VERSION 5.7 ;
NOWIREEXTENSIONATPIN ON ;
DIVIDERCHAR "/" ;
BUSBITCHARS "[]" ;

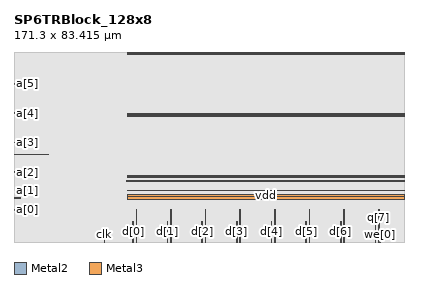
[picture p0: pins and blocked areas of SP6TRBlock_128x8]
MACRO SP6TRBlock_128x8
  CLASS BLOCK ;
  FOREIGN SP6TRBlock_128x8 ;
  ORIGIN 0.000 0.000 ;
  SIZE 171.300 BY 83.415 ;
  SYMMETRY X Y R90 ;
  PIN clk
  USE CLOCK ;
  DIRECTION INPUT ;
  ANTENNAGATEAREA 0.492800 ;
  PORT
      LAYER Metal2 ;
      RECT 39.515 0.000 39.895 1.900 ;
  END
  END clk
  PIN a[0]
  USE SIGNAL ;
  DIRECTION INPUT ;
  ANTENNAGATEAREA 0.492800 ;
  PORT
      LAYER Metal3 ;
      RECT 0.000 14.025 2.980 14.305 ;
  END
  END a[0]
  PIN a[1]
  USE SIGNAL ;
  DIRECTION INPUT ;
  ANTENNAGATEAREA 0.492800 ;
  PORT
      LAYER Metal3 ;
      RECT 0.000 19.165 2.980 19.445 ;
  END
  END a[1]
  PIN a[2]
  USE SIGNAL ;
  DIRECTION INPUT ;
  ANTENNAGATEAREA 0.492800 ;
  PORT
      LAYER Metal3 ;
      RECT 0.000 30.565 2.510 30.845 ;
  END
  END a[2]
  PIN a[3]
  USE SIGNAL ;
  DIRECTION INPUT ;
  ANTENNAGATEAREA 0.492800 ;
  PORT
      LAYER Metal3 ;
      RECT 0.000 43.485 2.510 43.765 ;
  END
  END a[3]
  PIN a[4]
  USE SIGNAL ;
  DIRECTION INPUT ;
  ANTENNAGATEAREA 0.492800 ;
  PORT
      LAYER Metal3 ;
      RECT 0.000 56.405 2.510 56.685 ;
  END
  END a[4]
  PIN a[5]
  USE SIGNAL ;
  DIRECTION INPUT ;
  ANTENNAGATEAREA 0.492800 ;
  PORT
      LAYER Metal3 ;
      RECT 0.000 69.325 2.510 69.605 ;
  END
  END a[5]
  PIN a[6]
  USE SIGNAL ;
  DIRECTION INPUT ;
  ANTENNAGATEAREA 0.492800 ;
  PORT
      LAYER Metal3 ;
      RECT 0.000 38.345 15.010 38.625 ;
  END
  END a[6]
  PIN d[0]
  USE SIGNAL ;
  DIRECTION INPUT ;
  ANTENNAGATEAREA 0.492800 ;
  PORT
      LAYER Metal3 ;
      RECT 52.130 0.000 52.410 9.140 ;
  END
  END d[0]
  PIN d[1]
  USE SIGNAL ;
  DIRECTION INPUT ;
  ANTENNAGATEAREA 0.492800 ;
  PORT
      LAYER Metal3 ;
      RECT 67.330 0.000 67.610 9.140 ;
  END
  END d[1]
  PIN d[2]
  USE SIGNAL ;
  DIRECTION INPUT ;
  ANTENNAGATEAREA 0.492800 ;
  PORT
      LAYER Metal3 ;
      RECT 82.530 0.000 82.810 9.140 ;
  END
  END d[2]
  PIN d[3]
  USE SIGNAL ;
  DIRECTION INPUT ;
  ANTENNAGATEAREA 0.492800 ;
  PORT
      LAYER Metal3 ;
      RECT 97.730 0.000 98.010 9.140 ;
  END
  END d[3]
  PIN d[4]
  USE SIGNAL ;
  DIRECTION INPUT ;
  ANTENNAGATEAREA 0.492800 ;
  PORT
      LAYER Metal3 ;
      RECT 112.930 0.000 113.210 9.140 ;
  END
  END d[4]
  PIN d[5]
  USE SIGNAL ;
  DIRECTION INPUT ;
  ANTENNAGATEAREA 0.492800 ;
  PORT
      LAYER Metal3 ;
      RECT 128.130 0.000 128.410 9.140 ;
  END
  END d[5]
  PIN d[6]
  USE SIGNAL ;
  DIRECTION INPUT ;
  ANTENNAGATEAREA 0.492800 ;
  PORT
      LAYER Metal3 ;
      RECT 143.330 0.000 143.610 9.140 ;
  END
  END d[6]
  PIN d[7]
  USE SIGNAL ;
  DIRECTION INPUT ;
  ANTENNAGATEAREA 0.492800 ;
  PORT
      LAYER Metal3 ;
      RECT 158.530 0.000 158.810 9.140 ;
  END
  END d[7]
  PIN we[0]
  USE SIGNAL ;
  DIRECTION INPUT ;
  ANTENNAGATEAREA 0.492800 ;
  PORT
      LAYER Metal3 ;
      RECT 160.550 0.000 160.830 1.000 ;
  END
  END we[0]
  PIN q[0]
  USE SIGNAL ;
  DIRECTION OUTPUT ;
  PORT
      LAYER Metal3 ;
      RECT 53.590 0.000 53.870 14.190 ;
  END
  END q[0]
  PIN q[1]
  USE SIGNAL ;
  DIRECTION OUTPUT ;
  PORT
      LAYER Metal3 ;
      RECT 68.790 0.000 69.070 14.190 ;
  END
  END q[1]
  PIN q[2]
  USE SIGNAL ;
  DIRECTION OUTPUT ;
  PORT
      LAYER Metal3 ;
      RECT 83.990 0.000 84.270 14.190 ;
  END
  END q[2]
  PIN q[3]
  USE SIGNAL ;
  DIRECTION OUTPUT ;
  PORT
      LAYER Metal3 ;
      RECT 99.190 0.000 99.470 14.190 ;
  END
  END q[3]
  PIN q[4]
  USE SIGNAL ;
  DIRECTION OUTPUT ;
  PORT
      LAYER Metal3 ;
      RECT 114.390 0.000 114.670 14.190 ;
  END
  END q[4]
  PIN q[5]
  USE SIGNAL ;
  DIRECTION OUTPUT ;
  PORT
      LAYER Metal3 ;
      RECT 129.590 0.000 129.870 14.190 ;
  END
  END q[5]
  PIN q[6]
  USE SIGNAL ;
  DIRECTION OUTPUT ;
  PORT
      LAYER Metal3 ;
      RECT 144.790 0.000 145.070 14.190 ;
  END
  END q[6]
  PIN q[7]
  USE SIGNAL ;
  DIRECTION OUTPUT ;
  PORT
      LAYER Metal3 ;
      RECT 159.990 0.000 160.270 14.190 ;
  END
  END q[7]
  PIN vss
    USE GROUND ;
    DIRECTION INOUT ;
    PORT
      LAYER Metal3 ;
        RECT 49.700 82.195 171.300 82.595 ;
    END
    PORT
      LAYER Metal3 ;
        RECT 49.700 55.235 171.300 55.635 ;
    END
    PORT
      LAYER Metal3 ;
        RECT 49.700 28.275 171.300 28.675 ;
    END
    PORT
      LAYER Metal3 ;
        RECT 49.700 22.450 171.300 22.730 ;
    END
    PORT
      LAYER Metal3 ;
        RECT 49.700 18.780 171.300 19.780 ;
    END
  END vss
  PIN vdd
    USE POWER ;
    DIRECTION INOUT ;
    PORT
      LAYER Metal3 ;
        RECT 49.700 20.060 171.300 21.060 ;
    END
    PORT
      LAYER Metal3 ;
        RECT 49.510 26.745 171.300 27.025 ;
    END
    PORT
      LAYER Metal3 ;
        RECT 49.700 55.915 171.300 56.315 ;
    END
    PORT
      LAYER Metal3 ;
        RECT 49.700 28.955 171.300 29.355 ;
    END
    PORT
      LAYER Metal3 ;
        RECT 49.700 82.875 171.300 83.275 ;
    END
  END vdd
  OBS
    LAYER Metal1 ;
      RECT 0.000 0.000 171.300 83.415 ;
    LAYER Metal2 ;
      RECT 0.000 0.000 171.300 83.415 ;
    LAYER Metal3 ;
      RECT 0.000 0.000 171.300 83.415 ;
  END
END SP6TRBlock_128x8

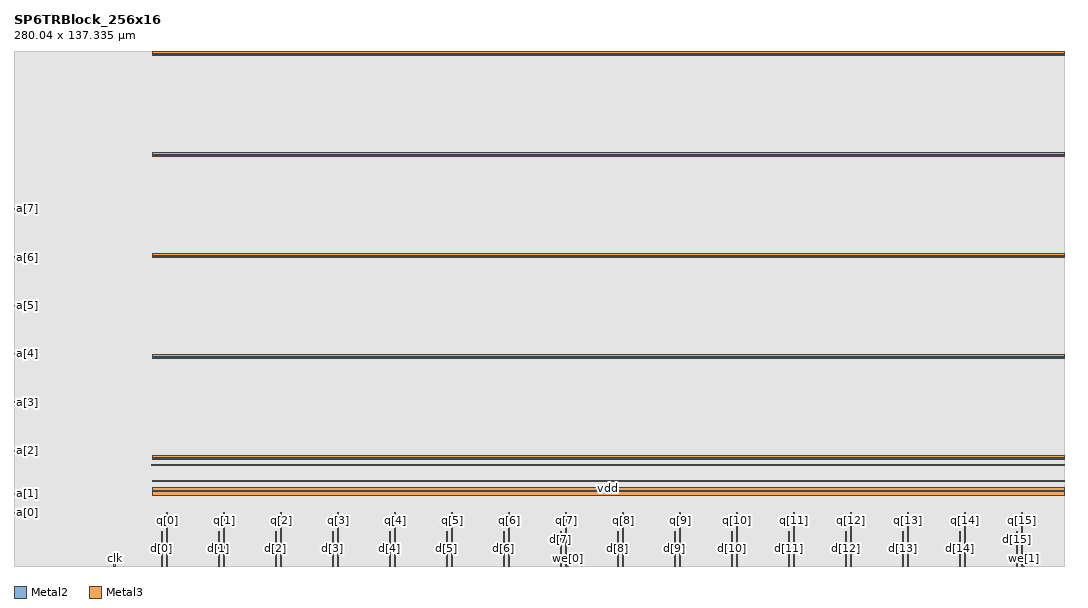
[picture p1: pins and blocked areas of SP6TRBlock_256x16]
MACRO SP6TRBlock_256x16
  CLASS BLOCK ;
  FOREIGN SP6TRBlock_256x16 ;
  ORIGIN 0.000 0.000 ;
  SIZE 280.040 BY 137.335 ;
  SYMMETRY X Y R90 ;
  PIN clk
  USE CLOCK ;
  DIRECTION INPUT ;
  ANTENNAGATEAREA 0.492800 ;
  PORT
      LAYER Metal2 ;
      RECT 26.655 0.000 27.035 1.900 ;
  END
  END clk
  PIN a[0]
  USE SIGNAL ;
  DIRECTION INPUT ;
  ANTENNAGATEAREA 0.492800 ;
  PORT
      LAYER Metal3 ;
      RECT 0.000 14.025 2.980 14.305 ;
  END
  END a[0]
  PIN a[1]
  USE SIGNAL ;
  DIRECTION INPUT ;
  ANTENNAGATEAREA 0.492800 ;
  PORT
      LAYER Metal3 ;
      RECT 0.000 19.165 2.980 19.445 ;
  END
  END a[1]
  PIN a[2]
  USE SIGNAL ;
  DIRECTION INPUT ;
  ANTENNAGATEAREA 0.492800 ;
  PORT
      LAYER Metal3 ;
      RECT 0.000 30.565 2.510 30.845 ;
  END
  END a[2]
  PIN a[3]
  USE SIGNAL ;
  DIRECTION INPUT ;
  ANTENNAGATEAREA 0.492800 ;
  PORT
      LAYER Metal3 ;
      RECT 0.000 43.485 2.510 43.765 ;
  END
  END a[3]
  PIN a[4]
  USE SIGNAL ;
  DIRECTION INPUT ;
  ANTENNAGATEAREA 0.492800 ;
  PORT
      LAYER Metal3 ;
      RECT 0.000 56.405 2.510 56.685 ;
  END
  END a[4]
  PIN a[5]
  USE SIGNAL ;
  DIRECTION INPUT ;
  ANTENNAGATEAREA 0.492800 ;
  PORT
      LAYER Metal3 ;
      RECT 0.000 69.325 2.510 69.605 ;
  END
  END a[5]
  PIN a[6]
  USE SIGNAL ;
  DIRECTION INPUT ;
  ANTENNAGATEAREA 0.492800 ;
  PORT
      LAYER Metal3 ;
      RECT 0.000 82.245 2.510 82.525 ;
  END
  END a[6]
  PIN a[7]
  USE SIGNAL ;
  DIRECTION INPUT ;
  ANTENNAGATEAREA 0.492800 ;
  PORT
      LAYER Metal3 ;
      RECT 0.000 95.165 2.510 95.445 ;
  END
  END a[7]
  PIN d[0]
  USE SIGNAL ;
  DIRECTION INPUT ;
  ANTENNAGATEAREA 0.492800 ;
  PORT
      LAYER Metal3 ;
      RECT 39.270 0.000 39.550 9.140 ;
  END
  END d[0]
  PIN d[1]
  USE SIGNAL ;
  DIRECTION INPUT ;
  ANTENNAGATEAREA 0.492800 ;
  PORT
      LAYER Metal3 ;
      RECT 54.470 0.000 54.750 9.140 ;
  END
  END d[1]
  PIN d[2]
  USE SIGNAL ;
  DIRECTION INPUT ;
  ANTENNAGATEAREA 0.492800 ;
  PORT
      LAYER Metal3 ;
      RECT 69.670 0.000 69.950 9.140 ;
  END
  END d[2]
  PIN d[3]
  USE SIGNAL ;
  DIRECTION INPUT ;
  ANTENNAGATEAREA 0.492800 ;
  PORT
      LAYER Metal3 ;
      RECT 84.870 0.000 85.150 9.140 ;
  END
  END d[3]
  PIN d[4]
  USE SIGNAL ;
  DIRECTION INPUT ;
  ANTENNAGATEAREA 0.492800 ;
  PORT
      LAYER Metal3 ;
      RECT 100.070 0.000 100.350 9.140 ;
  END
  END d[4]
  PIN d[5]
  USE SIGNAL ;
  DIRECTION INPUT ;
  ANTENNAGATEAREA 0.492800 ;
  PORT
      LAYER Metal3 ;
      RECT 115.270 0.000 115.550 9.140 ;
  END
  END d[5]
  PIN d[6]
  USE SIGNAL ;
  DIRECTION INPUT ;
  ANTENNAGATEAREA 0.492800 ;
  PORT
      LAYER Metal3 ;
      RECT 130.470 0.000 130.750 9.140 ;
  END
  END d[6]
  PIN d[7]
  USE SIGNAL ;
  DIRECTION INPUT ;
  ANTENNAGATEAREA 0.492800 ;
  PORT
      LAYER Metal3 ;
      RECT 145.670 0.000 145.950 9.140 ;
  END
  END d[7]
  PIN d[8]
  USE SIGNAL ;
  DIRECTION INPUT ;
  ANTENNAGATEAREA 0.492800 ;
  PORT
      LAYER Metal3 ;
      RECT 160.870 0.000 161.150 9.140 ;
  END
  END d[8]
  PIN d[9]
  USE SIGNAL ;
  DIRECTION INPUT ;
  ANTENNAGATEAREA 0.492800 ;
  PORT
      LAYER Metal3 ;
      RECT 176.070 0.000 176.350 9.140 ;
  END
  END d[9]
  PIN d[10]
  USE SIGNAL ;
  DIRECTION INPUT ;
  ANTENNAGATEAREA 0.492800 ;
  PORT
      LAYER Metal3 ;
      RECT 191.270 0.000 191.550 9.140 ;
  END
  END d[10]
  PIN d[11]
  USE SIGNAL ;
  DIRECTION INPUT ;
  ANTENNAGATEAREA 0.492800 ;
  PORT
      LAYER Metal3 ;
      RECT 206.470 0.000 206.750 9.140 ;
  END
  END d[11]
  PIN d[12]
  USE SIGNAL ;
  DIRECTION INPUT ;
  ANTENNAGATEAREA 0.492800 ;
  PORT
      LAYER Metal3 ;
      RECT 221.670 0.000 221.950 9.140 ;
  END
  END d[12]
  PIN d[13]
  USE SIGNAL ;
  DIRECTION INPUT ;
  ANTENNAGATEAREA 0.492800 ;
  PORT
      LAYER Metal3 ;
      RECT 236.870 0.000 237.150 9.140 ;
  END
  END d[13]
  PIN d[14]
  USE SIGNAL ;
  DIRECTION INPUT ;
  ANTENNAGATEAREA 0.492800 ;
  PORT
      LAYER Metal3 ;
      RECT 252.070 0.000 252.350 9.140 ;
  END
  END d[14]
  PIN d[15]
  USE SIGNAL ;
  DIRECTION INPUT ;
  ANTENNAGATEAREA 0.492800 ;
  PORT
      LAYER Metal3 ;
      RECT 267.270 0.000 267.550 9.140 ;
  END
  END d[15]
  PIN we[0]
  USE SIGNAL ;
  DIRECTION INPUT ;
  ANTENNAGATEAREA 0.492800 ;
  PORT
      LAYER Metal3 ;
      RECT 147.690 0.000 147.970 1.000 ;
  END
  END we[0]
  PIN we[1]
  USE SIGNAL ;
  DIRECTION INPUT ;
  ANTENNAGATEAREA 0.492800 ;
  PORT
      LAYER Metal3 ;
      RECT 269.290 0.000 269.570 1.000 ;
  END
  END we[1]
  PIN q[0]
  USE SIGNAL ;
  DIRECTION OUTPUT ;
  PORT
      LAYER Metal3 ;
      RECT 40.730 0.000 41.010 14.190 ;
  END
  END q[0]
  PIN q[1]
  USE SIGNAL ;
  DIRECTION OUTPUT ;
  PORT
      LAYER Metal3 ;
      RECT 55.930 0.000 56.210 14.190 ;
  END
  END q[1]
  PIN q[2]
  USE SIGNAL ;
  DIRECTION OUTPUT ;
  PORT
      LAYER Metal3 ;
      RECT 71.130 0.000 71.410 14.190 ;
  END
  END q[2]
  PIN q[3]
  USE SIGNAL ;
  DIRECTION OUTPUT ;
  PORT
      LAYER Metal3 ;
      RECT 86.330 0.000 86.610 14.190 ;
  END
  END q[3]
  PIN q[4]
  USE SIGNAL ;
  DIRECTION OUTPUT ;
  PORT
      LAYER Metal3 ;
      RECT 101.530 0.000 101.810 14.190 ;
  END
  END q[4]
  PIN q[5]
  USE SIGNAL ;
  DIRECTION OUTPUT ;
  PORT
      LAYER Metal3 ;
      RECT 116.730 0.000 117.010 14.190 ;
  END
  END q[5]
  PIN q[6]
  USE SIGNAL ;
  DIRECTION OUTPUT ;
  PORT
      LAYER Metal3 ;
      RECT 131.930 0.000 132.210 14.190 ;
  END
  END q[6]
  PIN q[7]
  USE SIGNAL ;
  DIRECTION OUTPUT ;
  PORT
      LAYER Metal3 ;
      RECT 147.130 0.000 147.410 14.190 ;
  END
  END q[7]
  PIN q[8]
  USE SIGNAL ;
  DIRECTION OUTPUT ;
  PORT
      LAYER Metal3 ;
      RECT 162.330 0.000 162.610 14.190 ;
  END
  END q[8]
  PIN q[9]
  USE SIGNAL ;
  DIRECTION OUTPUT ;
  PORT
      LAYER Metal3 ;
      RECT 177.530 0.000 177.810 14.190 ;
  END
  END q[9]
  PIN q[10]
  USE SIGNAL ;
  DIRECTION OUTPUT ;
  PORT
      LAYER Metal3 ;
      RECT 192.730 0.000 193.010 14.190 ;
  END
  END q[10]
  PIN q[11]
  USE SIGNAL ;
  DIRECTION OUTPUT ;
  PORT
      LAYER Metal3 ;
      RECT 207.930 0.000 208.210 14.190 ;
  END
  END q[11]
  PIN q[12]
  USE SIGNAL ;
  DIRECTION OUTPUT ;
  PORT
      LAYER Metal3 ;
      RECT 223.130 0.000 223.410 14.190 ;
  END
  END q[12]
  PIN q[13]
  USE SIGNAL ;
  DIRECTION OUTPUT ;
  PORT
      LAYER Metal3 ;
      RECT 238.330 0.000 238.610 14.190 ;
  END
  END q[13]
  PIN q[14]
  USE SIGNAL ;
  DIRECTION OUTPUT ;
  PORT
      LAYER Metal3 ;
      RECT 253.530 0.000 253.810 14.190 ;
  END
  END q[14]
  PIN q[15]
  USE SIGNAL ;
  DIRECTION OUTPUT ;
  PORT
      LAYER Metal3 ;
      RECT 268.730 0.000 269.010 14.190 ;
  END
  END q[15]
  PIN vss
    USE GROUND ;
    DIRECTION INOUT ;
    PORT
      LAYER Metal3 ;
        RECT 36.840 82.195 280.040 82.595 ;
    END
    PORT
      LAYER Metal3 ;
        RECT 36.840 136.115 280.040 136.515 ;
    END
    PORT
      LAYER Metal3 ;
        RECT 36.840 18.780 280.040 19.780 ;
    END
    PORT
      LAYER Metal3 ;
        RECT 36.840 55.235 280.040 55.635 ;
    END
    PORT
      LAYER Metal3 ;
        RECT 36.840 28.275 280.040 28.675 ;
    END
    PORT
      LAYER Metal3 ;
        RECT 36.840 109.155 280.040 109.555 ;
    END
    PORT
      LAYER Metal3 ;
        RECT 36.840 22.450 280.040 22.730 ;
    END
  END vss
  PIN vdd
    USE POWER ;
    DIRECTION INOUT ;
    PORT
      LAYER Metal3 ;
        RECT 36.840 109.835 280.040 110.235 ;
    END
    PORT
      LAYER Metal3 ;
        RECT 36.840 28.955 280.040 29.355 ;
    END
    PORT
      LAYER Metal3 ;
        RECT 36.650 26.745 280.040 27.025 ;
    END
    PORT
      LAYER Metal3 ;
        RECT 36.840 136.795 280.040 137.195 ;
    END
    PORT
      LAYER Metal3 ;
        RECT 36.840 82.875 280.040 83.275 ;
    END
    PORT
      LAYER Metal3 ;
        RECT 36.840 55.915 280.040 56.315 ;
    END
    PORT
      LAYER Metal3 ;
        RECT 36.840 20.060 280.040 21.060 ;
    END
  END vdd
  OBS
    LAYER Metal1 ;
      RECT 0.000 0.000 280.040 137.335 ;
    LAYER Metal2 ;
      RECT 0.000 0.000 280.040 137.335 ;
    LAYER Metal3 ;
      RECT 0.000 0.000 280.040 137.335 ;
  END
END SP6TRBlock_256x16

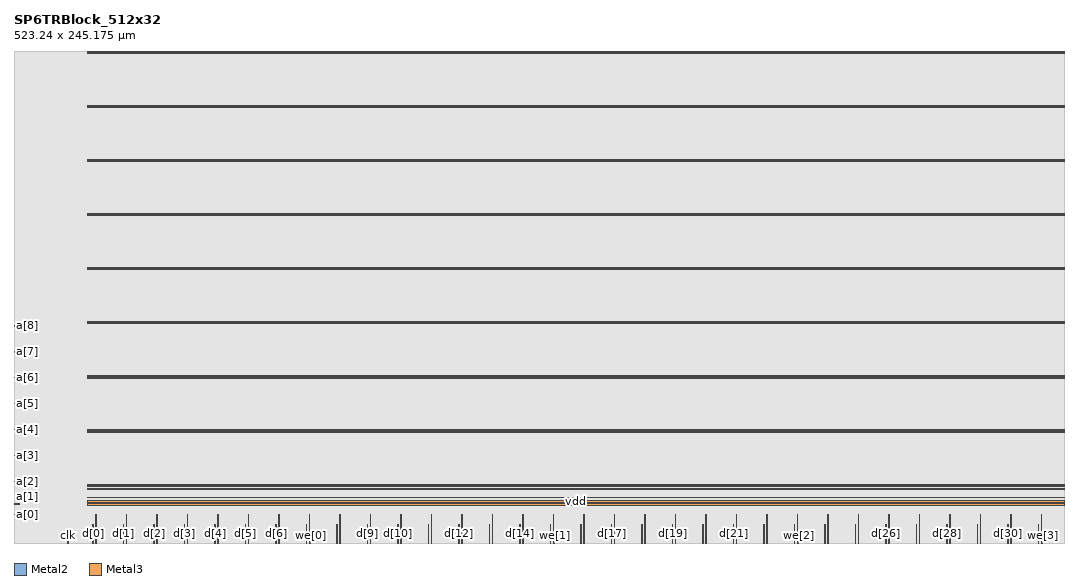
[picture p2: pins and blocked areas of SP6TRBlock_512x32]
MACRO SP6TRBlock_512x32
  CLASS BLOCK ;
  FOREIGN SP6TRBlock_512x32 ;
  ORIGIN 0.000 0.000 ;
  SIZE 523.240 BY 245.175 ;
  SYMMETRY X Y R90 ;
  PIN clk
  USE CLOCK ;
  DIRECTION INPUT ;
  ANTENNAGATEAREA 0.492800 ;
  PORT
      LAYER Metal2 ;
      RECT 26.655 0.000 27.035 1.900 ;
  END
  END clk
  PIN a[0]
  USE SIGNAL ;
  DIRECTION INPUT ;
  ANTENNAGATEAREA 0.492800 ;
  PORT
      LAYER Metal3 ;
      RECT 0.000 14.025 2.980 14.305 ;
  END
  END a[0]
  PIN a[1]
  USE SIGNAL ;
  DIRECTION INPUT ;
  ANTENNAGATEAREA 0.492800 ;
  PORT
      LAYER Metal3 ;
      RECT 0.000 19.165 2.980 19.445 ;
  END
  END a[1]
  PIN a[2]
  USE SIGNAL ;
  DIRECTION INPUT ;
  ANTENNAGATEAREA 0.492800 ;
  PORT
      LAYER Metal3 ;
      RECT 0.000 30.565 2.510 30.845 ;
  END
  END a[2]
  PIN a[3]
  USE SIGNAL ;
  DIRECTION INPUT ;
  ANTENNAGATEAREA 0.492800 ;
  PORT
      LAYER Metal3 ;
      RECT 0.000 43.485 2.510 43.765 ;
  END
  END a[3]
  PIN a[4]
  USE SIGNAL ;
  DIRECTION INPUT ;
  ANTENNAGATEAREA 0.492800 ;
  PORT
      LAYER Metal3 ;
      RECT 0.000 56.405 2.510 56.685 ;
  END
  END a[4]
  PIN a[5]
  USE SIGNAL ;
  DIRECTION INPUT ;
  ANTENNAGATEAREA 0.492800 ;
  PORT
      LAYER Metal3 ;
      RECT 0.000 69.325 2.510 69.605 ;
  END
  END a[5]
  PIN a[6]
  USE SIGNAL ;
  DIRECTION INPUT ;
  ANTENNAGATEAREA 0.492800 ;
  PORT
      LAYER Metal3 ;
      RECT 0.000 82.245 2.510 82.525 ;
  END
  END a[6]
  PIN a[7]
  USE SIGNAL ;
  DIRECTION INPUT ;
  ANTENNAGATEAREA 0.492800 ;
  PORT
      LAYER Metal3 ;
      RECT 0.000 95.165 2.510 95.445 ;
  END
  END a[7]
  PIN a[8]
  USE SIGNAL ;
  DIRECTION INPUT ;
  ANTENNAGATEAREA 0.492800 ;
  PORT
      LAYER Metal3 ;
      RECT 0.000 108.085 2.510 108.365 ;
  END
  END a[8]
  PIN d[0]
  USE SIGNAL ;
  DIRECTION INPUT ;
  ANTENNAGATEAREA 0.492800 ;
  PORT
      LAYER Metal3 ;
      RECT 39.270 0.000 39.550 9.140 ;
  END
  END d[0]
  PIN d[1]
  USE SIGNAL ;
  DIRECTION INPUT ;
  ANTENNAGATEAREA 0.492800 ;
  PORT
      LAYER Metal3 ;
      RECT 54.470 0.000 54.750 9.140 ;
  END
  END d[1]
  PIN d[2]
  USE SIGNAL ;
  DIRECTION INPUT ;
  ANTENNAGATEAREA 0.492800 ;
  PORT
      LAYER Metal3 ;
      RECT 69.670 0.000 69.950 9.140 ;
  END
  END d[2]
  PIN d[3]
  USE SIGNAL ;
  DIRECTION INPUT ;
  ANTENNAGATEAREA 0.492800 ;
  PORT
      LAYER Metal3 ;
      RECT 84.870 0.000 85.150 9.140 ;
  END
  END d[3]
  PIN d[4]
  USE SIGNAL ;
  DIRECTION INPUT ;
  ANTENNAGATEAREA 0.492800 ;
  PORT
      LAYER Metal3 ;
      RECT 100.070 0.000 100.350 9.140 ;
  END
  END d[4]
  PIN d[5]
  USE SIGNAL ;
  DIRECTION INPUT ;
  ANTENNAGATEAREA 0.492800 ;
  PORT
      LAYER Metal3 ;
      RECT 115.270 0.000 115.550 9.140 ;
  END
  END d[5]
  PIN d[6]
  USE SIGNAL ;
  DIRECTION INPUT ;
  ANTENNAGATEAREA 0.492800 ;
  PORT
      LAYER Metal3 ;
      RECT 130.470 0.000 130.750 9.140 ;
  END
  END d[6]
  PIN d[7]
  USE SIGNAL ;
  DIRECTION INPUT ;
  ANTENNAGATEAREA 0.492800 ;
  PORT
      LAYER Metal3 ;
      RECT 145.670 0.000 145.950 9.140 ;
  END
  END d[7]
  PIN d[8]
  USE SIGNAL ;
  DIRECTION INPUT ;
  ANTENNAGATEAREA 0.492800 ;
  PORT
      LAYER Metal3 ;
      RECT 160.870 0.000 161.150 9.140 ;
  END
  END d[8]
  PIN d[9]
  USE SIGNAL ;
  DIRECTION INPUT ;
  ANTENNAGATEAREA 0.492800 ;
  PORT
      LAYER Metal3 ;
      RECT 176.070 0.000 176.350 9.140 ;
  END
  END d[9]
  PIN d[10]
  USE SIGNAL ;
  DIRECTION INPUT ;
  ANTENNAGATEAREA 0.492800 ;
  PORT
      LAYER Metal3 ;
      RECT 191.270 0.000 191.550 9.140 ;
  END
  END d[10]
  PIN d[11]
  USE SIGNAL ;
  DIRECTION INPUT ;
  ANTENNAGATEAREA 0.492800 ;
  PORT
      LAYER Metal3 ;
      RECT 206.470 0.000 206.750 9.140 ;
  END
  END d[11]
  PIN d[12]
  USE SIGNAL ;
  DIRECTION INPUT ;
  ANTENNAGATEAREA 0.492800 ;
  PORT
      LAYER Metal3 ;
      RECT 221.670 0.000 221.950 9.140 ;
  END
  END d[12]
  PIN d[13]
  USE SIGNAL ;
  DIRECTION INPUT ;
  ANTENNAGATEAREA 0.492800 ;
  PORT
      LAYER Metal3 ;
      RECT 236.870 0.000 237.150 9.140 ;
  END
  END d[13]
  PIN d[14]
  USE SIGNAL ;
  DIRECTION INPUT ;
  ANTENNAGATEAREA 0.492800 ;
  PORT
      LAYER Metal3 ;
      RECT 252.070 0.000 252.350 9.140 ;
  END
  END d[14]
  PIN d[15]
  USE SIGNAL ;
  DIRECTION INPUT ;
  ANTENNAGATEAREA 0.492800 ;
  PORT
      LAYER Metal3 ;
      RECT 267.270 0.000 267.550 9.140 ;
  END
  END d[15]
  PIN d[16]
  USE SIGNAL ;
  DIRECTION INPUT ;
  ANTENNAGATEAREA 0.492800 ;
  PORT
      LAYER Metal3 ;
      RECT 282.470 0.000 282.750 9.140 ;
  END
  END d[16]
  PIN d[17]
  USE SIGNAL ;
  DIRECTION INPUT ;
  ANTENNAGATEAREA 0.492800 ;
  PORT
      LAYER Metal3 ;
      RECT 297.670 0.000 297.950 9.140 ;
  END
  END d[17]
  PIN d[18]
  USE SIGNAL ;
  DIRECTION INPUT ;
  ANTENNAGATEAREA 0.492800 ;
  PORT
      LAYER Metal3 ;
      RECT 312.870 0.000 313.150 9.140 ;
  END
  END d[18]
  PIN d[19]
  USE SIGNAL ;
  DIRECTION INPUT ;
  ANTENNAGATEAREA 0.492800 ;
  PORT
      LAYER Metal3 ;
      RECT 328.070 0.000 328.350 9.140 ;
  END
  END d[19]
  PIN d[20]
  USE SIGNAL ;
  DIRECTION INPUT ;
  ANTENNAGATEAREA 0.492800 ;
  PORT
      LAYER Metal3 ;
      RECT 343.270 0.000 343.550 9.140 ;
  END
  END d[20]
  PIN d[21]
  USE SIGNAL ;
  DIRECTION INPUT ;
  ANTENNAGATEAREA 0.492800 ;
  PORT
      LAYER Metal3 ;
      RECT 358.470 0.000 358.750 9.140 ;
  END
  END d[21]
  PIN d[22]
  USE SIGNAL ;
  DIRECTION INPUT ;
  ANTENNAGATEAREA 0.492800 ;
  PORT
      LAYER Metal3 ;
      RECT 373.670 0.000 373.950 9.140 ;
  END
  END d[22]
  PIN d[23]
  USE SIGNAL ;
  DIRECTION INPUT ;
  ANTENNAGATEAREA 0.492800 ;
  PORT
      LAYER Metal3 ;
      RECT 388.870 0.000 389.150 9.140 ;
  END
  END d[23]
  PIN d[24]
  USE SIGNAL ;
  DIRECTION INPUT ;
  ANTENNAGATEAREA 0.492800 ;
  PORT
      LAYER Metal3 ;
      RECT 404.070 0.000 404.350 9.140 ;
  END
  END d[24]
  PIN d[25]
  USE SIGNAL ;
  DIRECTION INPUT ;
  ANTENNAGATEAREA 0.492800 ;
  PORT
      LAYER Metal3 ;
      RECT 419.270 0.000 419.550 9.140 ;
  END
  END d[25]
  PIN d[26]
  USE SIGNAL ;
  DIRECTION INPUT ;
  ANTENNAGATEAREA 0.492800 ;
  PORT
      LAYER Metal3 ;
      RECT 434.470 0.000 434.750 9.140 ;
  END
  END d[26]
  PIN d[27]
  USE SIGNAL ;
  DIRECTION INPUT ;
  ANTENNAGATEAREA 0.492800 ;
  PORT
      LAYER Metal3 ;
      RECT 449.670 0.000 449.950 9.140 ;
  END
  END d[27]
  PIN d[28]
  USE SIGNAL ;
  DIRECTION INPUT ;
  ANTENNAGATEAREA 0.492800 ;
  PORT
      LAYER Metal3 ;
      RECT 464.870 0.000 465.150 9.140 ;
  END
  END d[28]
  PIN d[29]
  USE SIGNAL ;
  DIRECTION INPUT ;
  ANTENNAGATEAREA 0.492800 ;
  PORT
      LAYER Metal3 ;
      RECT 480.070 0.000 480.350 9.140 ;
  END
  END d[29]
  PIN d[30]
  USE SIGNAL ;
  DIRECTION INPUT ;
  ANTENNAGATEAREA 0.492800 ;
  PORT
      LAYER Metal3 ;
      RECT 495.270 0.000 495.550 9.140 ;
  END
  END d[30]
  PIN d[31]
  USE SIGNAL ;
  DIRECTION INPUT ;
  ANTENNAGATEAREA 0.492800 ;
  PORT
      LAYER Metal3 ;
      RECT 510.470 0.000 510.750 9.140 ;
  END
  END d[31]
  PIN we[0]
  USE SIGNAL ;
  DIRECTION INPUT ;
  ANTENNAGATEAREA 0.492800 ;
  PORT
      LAYER Metal3 ;
      RECT 147.690 0.000 147.970 1.000 ;
  END
  END we[0]
  PIN we[1]
  USE SIGNAL ;
  DIRECTION INPUT ;
  ANTENNAGATEAREA 0.492800 ;
  PORT
      LAYER Metal3 ;
      RECT 269.290 0.000 269.570 1.000 ;
  END
  END we[1]
  PIN we[2]
  USE SIGNAL ;
  DIRECTION INPUT ;
  ANTENNAGATEAREA 0.492800 ;
  PORT
      LAYER Metal3 ;
      RECT 390.890 0.000 391.170 1.000 ;
  END
  END we[2]
  PIN we[3]
  USE SIGNAL ;
  DIRECTION INPUT ;
  ANTENNAGATEAREA 0.492800 ;
  PORT
      LAYER Metal3 ;
      RECT 512.490 0.000 512.770 1.000 ;
  END
  END we[3]
  PIN q[0]
  USE SIGNAL ;
  DIRECTION OUTPUT ;
  PORT
      LAYER Metal3 ;
      RECT 40.730 0.000 41.010 14.190 ;
  END
  END q[0]
  PIN q[1]
  USE SIGNAL ;
  DIRECTION OUTPUT ;
  PORT
      LAYER Metal3 ;
      RECT 55.930 0.000 56.210 14.190 ;
  END
  END q[1]
  PIN q[2]
  USE SIGNAL ;
  DIRECTION OUTPUT ;
  PORT
      LAYER Metal3 ;
      RECT 71.130 0.000 71.410 14.190 ;
  END
  END q[2]
  PIN q[3]
  USE SIGNAL ;
  DIRECTION OUTPUT ;
  PORT
      LAYER Metal3 ;
      RECT 86.330 0.000 86.610 14.190 ;
  END
  END q[3]
  PIN q[4]
  USE SIGNAL ;
  DIRECTION OUTPUT ;
  PORT
      LAYER Metal3 ;
      RECT 101.530 0.000 101.810 14.190 ;
  END
  END q[4]
  PIN q[5]
  USE SIGNAL ;
  DIRECTION OUTPUT ;
  PORT
      LAYER Metal3 ;
      RECT 116.730 0.000 117.010 14.190 ;
  END
  END q[5]
  PIN q[6]
  USE SIGNAL ;
  DIRECTION OUTPUT ;
  PORT
      LAYER Metal3 ;
      RECT 131.930 0.000 132.210 14.190 ;
  END
  END q[6]
  PIN q[7]
  USE SIGNAL ;
  DIRECTION OUTPUT ;
  PORT
      LAYER Metal3 ;
      RECT 147.130 0.000 147.410 14.190 ;
  END
  END q[7]
  PIN q[8]
  USE SIGNAL ;
  DIRECTION OUTPUT ;
  PORT
      LAYER Metal3 ;
      RECT 162.330 0.000 162.610 14.190 ;
  END
  END q[8]
  PIN q[9]
  USE SIGNAL ;
  DIRECTION OUTPUT ;
  PORT
      LAYER Metal3 ;
      RECT 177.530 0.000 177.810 14.190 ;
  END
  END q[9]
  PIN q[10]
  USE SIGNAL ;
  DIRECTION OUTPUT ;
  PORT
      LAYER Metal3 ;
      RECT 192.730 0.000 193.010 14.190 ;
  END
  END q[10]
  PIN q[11]
  USE SIGNAL ;
  DIRECTION OUTPUT ;
  PORT
      LAYER Metal3 ;
      RECT 207.930 0.000 208.210 14.190 ;
  END
  END q[11]
  PIN q[12]
  USE SIGNAL ;
  DIRECTION OUTPUT ;
  PORT
      LAYER Metal3 ;
      RECT 223.130 0.000 223.410 14.190 ;
  END
  END q[12]
  PIN q[13]
  USE SIGNAL ;
  DIRECTION OUTPUT ;
  PORT
      LAYER Metal3 ;
      RECT 238.330 0.000 238.610 14.190 ;
  END
  END q[13]
  PIN q[14]
  USE SIGNAL ;
  DIRECTION OUTPUT ;
  PORT
      LAYER Metal3 ;
      RECT 253.530 0.000 253.810 14.190 ;
  END
  END q[14]
  PIN q[15]
  USE SIGNAL ;
  DIRECTION OUTPUT ;
  PORT
      LAYER Metal3 ;
      RECT 268.730 0.000 269.010 14.190 ;
  END
  END q[15]
  PIN q[16]
  USE SIGNAL ;
  DIRECTION OUTPUT ;
  PORT
      LAYER Metal3 ;
      RECT 283.930 0.000 284.210 14.190 ;
  END
  END q[16]
  PIN q[17]
  USE SIGNAL ;
  DIRECTION OUTPUT ;
  PORT
      LAYER Metal3 ;
      RECT 299.130 0.000 299.410 14.190 ;
  END
  END q[17]
  PIN q[18]
  USE SIGNAL ;
  DIRECTION OUTPUT ;
  PORT
      LAYER Metal3 ;
      RECT 314.330 0.000 314.610 14.190 ;
  END
  END q[18]
  PIN q[19]
  USE SIGNAL ;
  DIRECTION OUTPUT ;
  PORT
      LAYER Metal3 ;
      RECT 329.530 0.000 329.810 14.190 ;
  END
  END q[19]
  PIN q[20]
  USE SIGNAL ;
  DIRECTION OUTPUT ;
  PORT
      LAYER Metal3 ;
      RECT 344.730 0.000 345.010 14.190 ;
  END
  END q[20]
  PIN q[21]
  USE SIGNAL ;
  DIRECTION OUTPUT ;
  PORT
      LAYER Metal3 ;
      RECT 359.930 0.000 360.210 14.190 ;
  END
  END q[21]
  PIN q[22]
  USE SIGNAL ;
  DIRECTION OUTPUT ;
  PORT
      LAYER Metal3 ;
      RECT 375.130 0.000 375.410 14.190 ;
  END
  END q[22]
  PIN q[23]
  USE SIGNAL ;
  DIRECTION OUTPUT ;
  PORT
      LAYER Metal3 ;
      RECT 390.330 0.000 390.610 14.190 ;
  END
  END q[23]
  PIN q[24]
  USE SIGNAL ;
  DIRECTION OUTPUT ;
  PORT
      LAYER Metal3 ;
      RECT 405.530 0.000 405.810 14.190 ;
  END
  END q[24]
  PIN q[25]
  USE SIGNAL ;
  DIRECTION OUTPUT ;
  PORT
      LAYER Metal3 ;
      RECT 420.730 0.000 421.010 14.190 ;
  END
  END q[25]
  PIN q[26]
  USE SIGNAL ;
  DIRECTION OUTPUT ;
  PORT
      LAYER Metal3 ;
      RECT 435.930 0.000 436.210 14.190 ;
  END
  END q[26]
  PIN q[27]
  USE SIGNAL ;
  DIRECTION OUTPUT ;
  PORT
      LAYER Metal3 ;
      RECT 451.130 0.000 451.410 14.190 ;
  END
  END q[27]
  PIN q[28]
  USE SIGNAL ;
  DIRECTION OUTPUT ;
  PORT
      LAYER Metal3 ;
      RECT 466.330 0.000 466.610 14.190 ;
  END
  END q[28]
  PIN q[29]
  USE SIGNAL ;
  DIRECTION OUTPUT ;
  PORT
      LAYER Metal3 ;
      RECT 481.530 0.000 481.810 14.190 ;
  END
  END q[29]
  PIN q[30]
  USE SIGNAL ;
  DIRECTION OUTPUT ;
  PORT
      LAYER Metal3 ;
      RECT 496.730 0.000 497.010 14.190 ;
  END
  END q[30]
  PIN q[31]
  USE SIGNAL ;
  DIRECTION OUTPUT ;
  PORT
      LAYER Metal3 ;
      RECT 511.930 0.000 512.210 14.190 ;
  END
  END q[31]
  PIN vss
    USE GROUND ;
    DIRECTION INOUT ;
    PORT
      LAYER Metal3 ;
        RECT 36.840 243.955 523.240 244.355 ;
    END
    PORT
      LAYER Metal3 ;
        RECT 36.840 136.115 523.240 136.515 ;
    END
    PORT
      LAYER Metal3 ;
        RECT 36.840 82.195 523.240 82.595 ;
    END
    PORT
      LAYER Metal3 ;
        RECT 36.840 18.780 523.240 19.780 ;
    END
    PORT
      LAYER Metal3 ;
        RECT 36.840 55.235 523.240 55.635 ;
    END
    PORT
      LAYER Metal3 ;
        RECT 36.840 216.995 523.240 217.395 ;
    END
    PORT
      LAYER Metal3 ;
        RECT 36.840 28.275 523.240 28.675 ;
    END
    PORT
      LAYER Metal3 ;
        RECT 36.840 109.155 523.240 109.555 ;
    END
    PORT
      LAYER Metal3 ;
        RECT 36.840 22.450 523.240 22.730 ;
    END
    PORT
      LAYER Metal3 ;
        RECT 36.840 190.035 523.240 190.435 ;
    END
    PORT
      LAYER Metal3 ;
        RECT 36.840 163.075 523.240 163.475 ;
    END
  END vss
  PIN vdd
    USE POWER ;
    DIRECTION INOUT ;
    PORT
      LAYER Metal3 ;
        RECT 36.840 20.060 523.240 21.060 ;
    END
    PORT
      LAYER Metal3 ;
        RECT 36.840 28.955 523.240 29.355 ;
    END
    PORT
      LAYER Metal3 ;
        RECT 36.840 244.635 523.240 245.035 ;
    END
    PORT
      LAYER Metal3 ;
        RECT 36.650 26.745 523.240 27.025 ;
    END
    PORT
      LAYER Metal3 ;
        RECT 36.840 190.715 523.240 191.115 ;
    END
    PORT
      LAYER Metal3 ;
        RECT 36.840 217.675 523.240 218.075 ;
    END
    PORT
      LAYER Metal3 ;
        RECT 36.840 109.835 523.240 110.235 ;
    END
    PORT
      LAYER Metal3 ;
        RECT 36.840 163.755 523.240 164.155 ;
    END
    PORT
      LAYER Metal3 ;
        RECT 36.840 136.795 523.240 137.195 ;
    END
    PORT
      LAYER Metal3 ;
        RECT 36.840 82.875 523.240 83.275 ;
    END
    PORT
      LAYER Metal3 ;
        RECT 36.840 55.915 523.240 56.315 ;
    END
  END vdd
  OBS
    LAYER Metal1 ;
      RECT 0.000 0.000 523.240 245.175 ;
    LAYER Metal2 ;
      RECT 0.000 0.000 523.240 245.175 ;
    LAYER Metal3 ;
      RECT 0.000 0.000 523.240 245.175 ;
  END
END SP6TRBlock_512x32

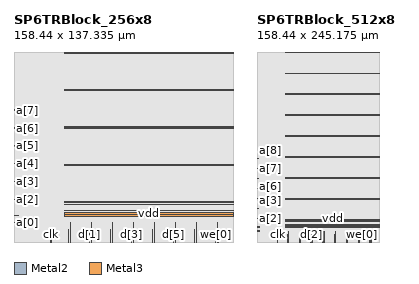
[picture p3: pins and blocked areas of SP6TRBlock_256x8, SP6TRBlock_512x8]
MACRO SP6TRBlock_256x8
  CLASS BLOCK ;
  FOREIGN SP6TRBlock_256x8 ;
  ORIGIN 0.000 0.000 ;
  SIZE 158.440 BY 137.335 ;
  SYMMETRY X Y R90 ;
  PIN clk
  USE CLOCK ;
  DIRECTION INPUT ;
  ANTENNAGATEAREA 0.492800 ;
  PORT
      LAYER Metal2 ;
      RECT 26.655 0.000 27.035 1.900 ;
  END
  END clk
  PIN a[0]
  USE SIGNAL ;
  DIRECTION INPUT ;
  ANTENNAGATEAREA 0.492800 ;
  PORT
      LAYER Metal3 ;
      RECT 0.000 14.025 2.980 14.305 ;
  END
  END a[0]
  PIN a[1]
  USE SIGNAL ;
  DIRECTION INPUT ;
  ANTENNAGATEAREA 0.492800 ;
  PORT
      LAYER Metal3 ;
      RECT 0.000 19.165 2.980 19.445 ;
  END
  END a[1]
  PIN a[2]
  USE SIGNAL ;
  DIRECTION INPUT ;
  ANTENNAGATEAREA 0.492800 ;
  PORT
      LAYER Metal3 ;
      RECT 0.000 30.565 2.510 30.845 ;
  END
  END a[2]
  PIN a[3]
  USE SIGNAL ;
  DIRECTION INPUT ;
  ANTENNAGATEAREA 0.492800 ;
  PORT
      LAYER Metal3 ;
      RECT 0.000 43.485 2.510 43.765 ;
  END
  END a[3]
  PIN a[4]
  USE SIGNAL ;
  DIRECTION INPUT ;
  ANTENNAGATEAREA 0.492800 ;
  PORT
      LAYER Metal3 ;
      RECT 0.000 56.405 2.510 56.685 ;
  END
  END a[4]
  PIN a[5]
  USE SIGNAL ;
  DIRECTION INPUT ;
  ANTENNAGATEAREA 0.492800 ;
  PORT
      LAYER Metal3 ;
      RECT 0.000 69.325 2.510 69.605 ;
  END
  END a[5]
  PIN a[6]
  USE SIGNAL ;
  DIRECTION INPUT ;
  ANTENNAGATEAREA 0.492800 ;
  PORT
      LAYER Metal3 ;
      RECT 0.000 82.245 2.510 82.525 ;
  END
  END a[6]
  PIN a[7]
  USE SIGNAL ;
  DIRECTION INPUT ;
  ANTENNAGATEAREA 0.492800 ;
  PORT
      LAYER Metal3 ;
      RECT 0.000 95.165 2.510 95.445 ;
  END
  END a[7]
  PIN d[0]
  USE SIGNAL ;
  DIRECTION INPUT ;
  ANTENNAGATEAREA 0.492800 ;
  PORT
      LAYER Metal3 ;
      RECT 39.270 0.000 39.550 9.140 ;
  END
  END d[0]
  PIN d[1]
  USE SIGNAL ;
  DIRECTION INPUT ;
  ANTENNAGATEAREA 0.492800 ;
  PORT
      LAYER Metal3 ;
      RECT 54.470 0.000 54.750 9.140 ;
  END
  END d[1]
  PIN d[2]
  USE SIGNAL ;
  DIRECTION INPUT ;
  ANTENNAGATEAREA 0.492800 ;
  PORT
      LAYER Metal3 ;
      RECT 69.670 0.000 69.950 9.140 ;
  END
  END d[2]
  PIN d[3]
  USE SIGNAL ;
  DIRECTION INPUT ;
  ANTENNAGATEAREA 0.492800 ;
  PORT
      LAYER Metal3 ;
      RECT 84.870 0.000 85.150 9.140 ;
  END
  END d[3]
  PIN d[4]
  USE SIGNAL ;
  DIRECTION INPUT ;
  ANTENNAGATEAREA 0.492800 ;
  PORT
      LAYER Metal3 ;
      RECT 100.070 0.000 100.350 9.140 ;
  END
  END d[4]
  PIN d[5]
  USE SIGNAL ;
  DIRECTION INPUT ;
  ANTENNAGATEAREA 0.492800 ;
  PORT
      LAYER Metal3 ;
      RECT 115.270 0.000 115.550 9.140 ;
  END
  END d[5]
  PIN d[6]
  USE SIGNAL ;
  DIRECTION INPUT ;
  ANTENNAGATEAREA 0.492800 ;
  PORT
      LAYER Metal3 ;
      RECT 130.470 0.000 130.750 9.140 ;
  END
  END d[6]
  PIN d[7]
  USE SIGNAL ;
  DIRECTION INPUT ;
  ANTENNAGATEAREA 0.492800 ;
  PORT
      LAYER Metal3 ;
      RECT 145.670 0.000 145.950 9.140 ;
  END
  END d[7]
  PIN we[0]
  USE SIGNAL ;
  DIRECTION INPUT ;
  ANTENNAGATEAREA 0.492800 ;
  PORT
      LAYER Metal3 ;
      RECT 147.690 0.000 147.970 1.000 ;
  END
  END we[0]
  PIN q[0]
  USE SIGNAL ;
  DIRECTION OUTPUT ;
  PORT
      LAYER Metal3 ;
      RECT 40.730 0.000 41.010 14.190 ;
  END
  END q[0]
  PIN q[1]
  USE SIGNAL ;
  DIRECTION OUTPUT ;
  PORT
      LAYER Metal3 ;
      RECT 55.930 0.000 56.210 14.190 ;
  END
  END q[1]
  PIN q[2]
  USE SIGNAL ;
  DIRECTION OUTPUT ;
  PORT
      LAYER Metal3 ;
      RECT 71.130 0.000 71.410 14.190 ;
  END
  END q[2]
  PIN q[3]
  USE SIGNAL ;
  DIRECTION OUTPUT ;
  PORT
      LAYER Metal3 ;
      RECT 86.330 0.000 86.610 14.190 ;
  END
  END q[3]
  PIN q[4]
  USE SIGNAL ;
  DIRECTION OUTPUT ;
  PORT
      LAYER Metal3 ;
      RECT 101.530 0.000 101.810 14.190 ;
  END
  END q[4]
  PIN q[5]
  USE SIGNAL ;
  DIRECTION OUTPUT ;
  PORT
      LAYER Metal3 ;
      RECT 116.730 0.000 117.010 14.190 ;
  END
  END q[5]
  PIN q[6]
  USE SIGNAL ;
  DIRECTION OUTPUT ;
  PORT
      LAYER Metal3 ;
      RECT 131.930 0.000 132.210 14.190 ;
  END
  END q[6]
  PIN q[7]
  USE SIGNAL ;
  DIRECTION OUTPUT ;
  PORT
      LAYER Metal3 ;
      RECT 147.130 0.000 147.410 14.190 ;
  END
  END q[7]
  PIN vss
    USE GROUND ;
    DIRECTION INOUT ;
    PORT
      LAYER Metal3 ;
        RECT 36.840 136.115 158.440 136.515 ;
    END
    PORT
      LAYER Metal3 ;
        RECT 36.840 55.235 158.440 55.635 ;
    END
    PORT
      LAYER Metal3 ;
        RECT 36.840 109.155 158.440 109.555 ;
    END
    PORT
      LAYER Metal3 ;
        RECT 36.840 82.195 158.440 82.595 ;
    END
    PORT
      LAYER Metal3 ;
        RECT 36.840 28.275 158.440 28.675 ;
    END
    PORT
      LAYER Metal3 ;
        RECT 36.840 18.780 158.440 19.780 ;
    END
    PORT
      LAYER Metal3 ;
        RECT 36.840 22.450 158.440 22.730 ;
    END
  END vss
  PIN vdd
    USE POWER ;
    DIRECTION INOUT ;
    PORT
      LAYER Metal3 ;
        RECT 36.840 55.915 158.440 56.315 ;
    END
    PORT
      LAYER Metal3 ;
        RECT 36.840 82.875 158.440 83.275 ;
    END
    PORT
      LAYER Metal3 ;
        RECT 36.840 136.795 158.440 137.195 ;
    END
    PORT
      LAYER Metal3 ;
        RECT 36.840 20.060 158.440 21.060 ;
    END
    PORT
      LAYER Metal3 ;
        RECT 36.650 26.745 158.440 27.025 ;
    END
    PORT
      LAYER Metal3 ;
        RECT 36.840 109.835 158.440 110.235 ;
    END
    PORT
      LAYER Metal3 ;
        RECT 36.840 28.955 158.440 29.355 ;
    END
  END vdd
  OBS
    LAYER Metal1 ;
      RECT 0.000 0.000 158.440 137.335 ;
    LAYER Metal2 ;
      RECT 0.000 0.000 158.440 137.335 ;
    LAYER Metal3 ;
      RECT 0.000 0.000 158.440 137.335 ;
  END
END SP6TRBlock_256x8

MACRO SP6TRBlock_512x8
  CLASS BLOCK ;
  FOREIGN SP6TRBlock_512x8 ;
  ORIGIN 0.000 0.000 ;
  SIZE 158.440 BY 245.175 ;
  SYMMETRY X Y R90 ;
  PIN clk
  USE CLOCK ;
  DIRECTION INPUT ;
  ANTENNAGATEAREA 0.492800 ;
  PORT
      LAYER Metal2 ;
      RECT 26.655 0.000 27.035 1.900 ;
  END
  END clk
  PIN a[0]
  USE SIGNAL ;
  DIRECTION INPUT ;
  ANTENNAGATEAREA 0.492800 ;
  PORT
      LAYER Metal3 ;
      RECT 0.000 14.025 2.980 14.305 ;
  END
  END a[0]
  PIN a[1]
  USE SIGNAL ;
  DIRECTION INPUT ;
  ANTENNAGATEAREA 0.492800 ;
  PORT
      LAYER Metal3 ;
      RECT 0.000 19.165 2.980 19.445 ;
  END
  END a[1]
  PIN a[2]
  USE SIGNAL ;
  DIRECTION INPUT ;
  ANTENNAGATEAREA 0.492800 ;
  PORT
      LAYER Metal3 ;
      RECT 0.000 30.565 2.510 30.845 ;
  END
  END a[2]
  PIN a[3]
  USE SIGNAL ;
  DIRECTION INPUT ;
  ANTENNAGATEAREA 0.492800 ;
  PORT
      LAYER Metal3 ;
      RECT 0.000 43.485 2.510 43.765 ;
  END
  END a[3]
  PIN a[4]
  USE SIGNAL ;
  DIRECTION INPUT ;
  ANTENNAGATEAREA 0.492800 ;
  PORT
      LAYER Metal3 ;
      RECT 0.000 56.405 2.510 56.685 ;
  END
  END a[4]
  PIN a[5]
  USE SIGNAL ;
  DIRECTION INPUT ;
  ANTENNAGATEAREA 0.492800 ;
  PORT
      LAYER Metal3 ;
      RECT 0.000 69.325 2.510 69.605 ;
  END
  END a[5]
  PIN a[6]
  USE SIGNAL ;
  DIRECTION INPUT ;
  ANTENNAGATEAREA 0.492800 ;
  PORT
      LAYER Metal3 ;
      RECT 0.000 82.245 2.510 82.525 ;
  END
  END a[6]
  PIN a[7]
  USE SIGNAL ;
  DIRECTION INPUT ;
  ANTENNAGATEAREA 0.492800 ;
  PORT
      LAYER Metal3 ;
      RECT 0.000 95.165 2.510 95.445 ;
  END
  END a[7]
  PIN a[8]
  USE SIGNAL ;
  DIRECTION INPUT ;
  ANTENNAGATEAREA 0.492800 ;
  PORT
      LAYER Metal3 ;
      RECT 0.000 108.085 2.510 108.365 ;
  END
  END a[8]
  PIN d[0]
  USE SIGNAL ;
  DIRECTION INPUT ;
  ANTENNAGATEAREA 0.492800 ;
  PORT
      LAYER Metal3 ;
      RECT 39.270 0.000 39.550 9.140 ;
  END
  END d[0]
  PIN d[1]
  USE SIGNAL ;
  DIRECTION INPUT ;
  ANTENNAGATEAREA 0.492800 ;
  PORT
      LAYER Metal3 ;
      RECT 54.470 0.000 54.750 9.140 ;
  END
  END d[1]
  PIN d[2]
  USE SIGNAL ;
  DIRECTION INPUT ;
  ANTENNAGATEAREA 0.492800 ;
  PORT
      LAYER Metal3 ;
      RECT 69.670 0.000 69.950 9.140 ;
  END
  END d[2]
  PIN d[3]
  USE SIGNAL ;
  DIRECTION INPUT ;
  ANTENNAGATEAREA 0.492800 ;
  PORT
      LAYER Metal3 ;
      RECT 84.870 0.000 85.150 9.140 ;
  END
  END d[3]
  PIN d[4]
  USE SIGNAL ;
  DIRECTION INPUT ;
  ANTENNAGATEAREA 0.492800 ;
  PORT
      LAYER Metal3 ;
      RECT 100.070 0.000 100.350 9.140 ;
  END
  END d[4]
  PIN d[5]
  USE SIGNAL ;
  DIRECTION INPUT ;
  ANTENNAGATEAREA 0.492800 ;
  PORT
      LAYER Metal3 ;
      RECT 115.270 0.000 115.550 9.140 ;
  END
  END d[5]
  PIN d[6]
  USE SIGNAL ;
  DIRECTION INPUT ;
  ANTENNAGATEAREA 0.492800 ;
  PORT
      LAYER Metal3 ;
      RECT 130.470 0.000 130.750 9.140 ;
  END
  END d[6]
  PIN d[7]
  USE SIGNAL ;
  DIRECTION INPUT ;
  ANTENNAGATEAREA 0.492800 ;
  PORT
      LAYER Metal3 ;
      RECT 145.670 0.000 145.950 9.140 ;
  END
  END d[7]
  PIN we[0]
  USE SIGNAL ;
  DIRECTION INPUT ;
  ANTENNAGATEAREA 0.492800 ;
  PORT
      LAYER Metal3 ;
      RECT 147.690 0.000 147.970 1.000 ;
  END
  END we[0]
  PIN q[0]
  USE SIGNAL ;
  DIRECTION OUTPUT ;
  PORT
      LAYER Metal3 ;
      RECT 40.730 0.000 41.010 14.190 ;
  END
  END q[0]
  PIN q[1]
  USE SIGNAL ;
  DIRECTION OUTPUT ;
  PORT
      LAYER Metal3 ;
      RECT 55.930 0.000 56.210 14.190 ;
  END
  END q[1]
  PIN q[2]
  USE SIGNAL ;
  DIRECTION OUTPUT ;
  PORT
      LAYER Metal3 ;
      RECT 71.130 0.000 71.410 14.190 ;
  END
  END q[2]
  PIN q[3]
  USE SIGNAL ;
  DIRECTION OUTPUT ;
  PORT
      LAYER Metal3 ;
      RECT 86.330 0.000 86.610 14.190 ;
  END
  END q[3]
  PIN q[4]
  USE SIGNAL ;
  DIRECTION OUTPUT ;
  PORT
      LAYER Metal3 ;
      RECT 101.530 0.000 101.810 14.190 ;
  END
  END q[4]
  PIN q[5]
  USE SIGNAL ;
  DIRECTION OUTPUT ;
  PORT
      LAYER Metal3 ;
      RECT 116.730 0.000 117.010 14.190 ;
  END
  END q[5]
  PIN q[6]
  USE SIGNAL ;
  DIRECTION OUTPUT ;
  PORT
      LAYER Metal3 ;
      RECT 131.930 0.000 132.210 14.190 ;
  END
  END q[6]
  PIN q[7]
  USE SIGNAL ;
  DIRECTION OUTPUT ;
  PORT
      LAYER Metal3 ;
      RECT 147.130 0.000 147.410 14.190 ;
  END
  END q[7]
  PIN vss
    USE GROUND ;
    DIRECTION INOUT ;
    PORT
      LAYER Metal3 ;
        RECT 36.840 190.035 158.440 190.435 ;
    END
    PORT
      LAYER Metal3 ;
        RECT 36.840 163.075 158.440 163.475 ;
    END
    PORT
      LAYER Metal3 ;
        RECT 36.840 136.115 158.440 136.515 ;
    END
    PORT
      LAYER Metal3 ;
        RECT 36.840 55.235 158.440 55.635 ;
    END
    PORT
      LAYER Metal3 ;
        RECT 36.840 216.995 158.440 217.395 ;
    END
    PORT
      LAYER Metal3 ;
        RECT 36.840 109.155 158.440 109.555 ;
    END
    PORT
      LAYER Metal3 ;
        RECT 36.840 243.955 158.440 244.355 ;
    END
    PORT
      LAYER Metal3 ;
        RECT 36.840 82.195 158.440 82.595 ;
    END
    PORT
      LAYER Metal3 ;
        RECT 36.840 28.275 158.440 28.675 ;
    END
    PORT
      LAYER Metal3 ;
        RECT 36.840 18.780 158.440 19.780 ;
    END
    PORT
      LAYER Metal3 ;
        RECT 36.840 22.450 158.440 22.730 ;
    END
  END vss
  PIN vdd
    USE POWER ;
    DIRECTION INOUT ;
    PORT
      LAYER Metal3 ;
        RECT 36.840 55.915 158.440 56.315 ;
    END
    PORT
      LAYER Metal3 ;
        RECT 36.840 82.875 158.440 83.275 ;
    END
    PORT
      LAYER Metal3 ;
        RECT 36.840 136.795 158.440 137.195 ;
    END
    PORT
      LAYER Metal3 ;
        RECT 36.840 163.755 158.440 164.155 ;
    END
    PORT
      LAYER Metal3 ;
        RECT 36.840 244.635 158.440 245.035 ;
    END
    PORT
      LAYER Metal3 ;
        RECT 36.840 20.060 158.440 21.060 ;
    END
    PORT
      LAYER Metal3 ;
        RECT 36.650 26.745 158.440 27.025 ;
    END
    PORT
      LAYER Metal3 ;
        RECT 36.840 217.675 158.440 218.075 ;
    END
    PORT
      LAYER Metal3 ;
        RECT 36.840 109.835 158.440 110.235 ;
    END
    PORT
      LAYER Metal3 ;
        RECT 36.840 28.955 158.440 29.355 ;
    END
    PORT
      LAYER Metal3 ;
        RECT 36.840 190.715 158.440 191.115 ;
    END
  END vdd
  OBS
    LAYER Metal1 ;
      RECT 0.000 0.000 158.440 245.175 ;
    LAYER Metal2 ;
      RECT 0.000 0.000 158.440 245.175 ;
    LAYER Metal3 ;
      RECT 0.000 0.000 158.440 245.175 ;
  END
END SP6TRBlock_512x8

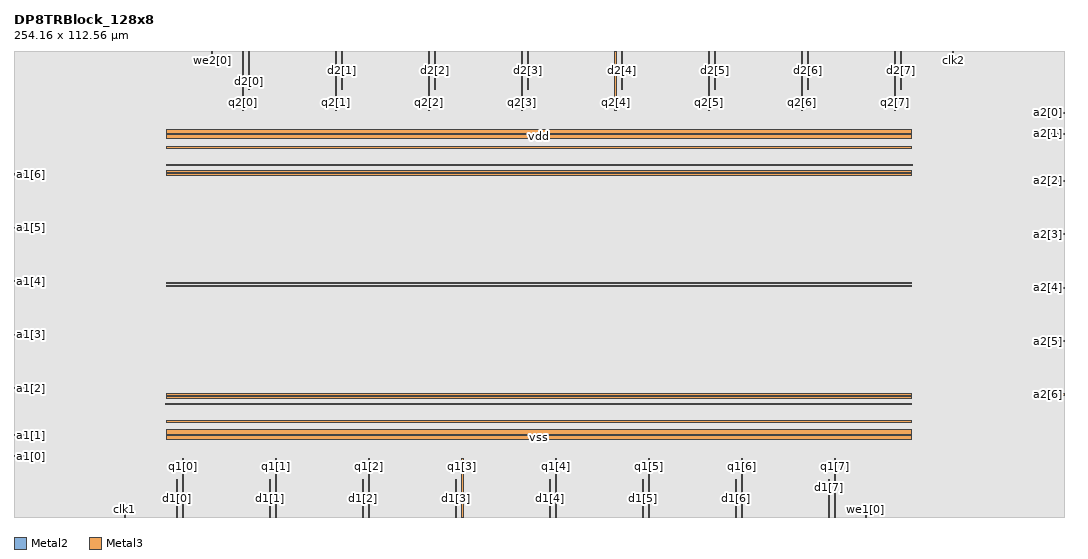
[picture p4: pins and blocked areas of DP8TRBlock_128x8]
MACRO DP8TRBlock_128x8
  CLASS BLOCK ;
  FOREIGN DP8TRBlock_128x8 ;
  ORIGIN 0.000 0.000 ;
  SIZE 254.160 BY 112.560 ;
  SYMMETRY X Y R90 ;
  PIN clk1
  USE CLOCK ;
  DIRECTION INPUT ;
  ANTENNAGATEAREA 0.492800 ;
  PORT
      LAYER Metal2 ;
      RECT 26.655 0.000 27.035 1.900 ;
  END
  END clk1
  PIN clk2
  USE CLOCK ;
  DIRECTION INPUT ;
  ANTENNAGATEAREA 0.492800 ;
  PORT
      LAYER Metal2 ;
      RECT 227.125 110.660 227.505 112.560 ;
  END
  END clk2
  PIN a1[0]
  USE SIGNAL ;
  DIRECTION INPUT ;
  ANTENNAGATEAREA 0.492800 ;
  PORT
      LAYER Metal3 ;
      RECT 0.000 14.530 2.980 14.810 ;
  END
  END a1[0]
  PIN a1[1]
  USE SIGNAL ;
  DIRECTION INPUT ;
  ANTENNAGATEAREA 0.492800 ;
  PORT
      LAYER Metal3 ;
      RECT 0.000 19.670 2.980 19.950 ;
  END
  END a1[1]
  PIN a1[2]
  USE SIGNAL ;
  DIRECTION INPUT ;
  ANTENNAGATEAREA 0.492800 ;
  PORT
      LAYER Metal3 ;
      RECT 0.000 31.070 2.510 31.350 ;
  END
  END a1[2]
  PIN a1[3]
  USE SIGNAL ;
  DIRECTION INPUT ;
  ANTENNAGATEAREA 0.492800 ;
  PORT
      LAYER Metal3 ;
      RECT 0.000 43.990 2.510 44.270 ;
  END
  END a1[3]
  PIN a1[4]
  USE SIGNAL ;
  DIRECTION INPUT ;
  ANTENNAGATEAREA 0.492800 ;
  PORT
      LAYER Metal3 ;
      RECT 0.000 56.910 2.510 57.190 ;
  END
  END a1[4]
  PIN a1[5]
  USE SIGNAL ;
  DIRECTION INPUT ;
  ANTENNAGATEAREA 0.492800 ;
  PORT
      LAYER Metal3 ;
      RECT 0.000 69.830 2.510 70.110 ;
  END
  END a1[5]
  PIN a1[6]
  USE SIGNAL ;
  DIRECTION INPUT ;
  ANTENNAGATEAREA 0.492800 ;
  PORT
      LAYER Metal3 ;
      RECT 0.000 82.750 2.510 83.030 ;
  END
  END a1[6]
  PIN d1[0]
  USE SIGNAL ;
  DIRECTION INPUT ;
  ANTENNAGATEAREA 0.492800 ;
  PORT
      LAYER Metal3 ;
      RECT 39.270 0.000 39.550 9.140 ;
  END
  END d1[0]
  PIN d1[1]
  USE SIGNAL ;
  DIRECTION INPUT ;
  ANTENNAGATEAREA 0.492800 ;
  PORT
      LAYER Metal3 ;
      RECT 61.830 0.000 62.110 9.140 ;
  END
  END d1[1]
  PIN d1[2]
  USE SIGNAL ;
  DIRECTION INPUT ;
  ANTENNAGATEAREA 0.492800 ;
  PORT
      LAYER Metal3 ;
      RECT 84.390 0.000 84.670 9.140 ;
  END
  END d1[2]
  PIN d1[3]
  USE SIGNAL ;
  DIRECTION INPUT ;
  ANTENNAGATEAREA 0.492800 ;
  PORT
      LAYER Metal3 ;
      RECT 106.950 0.000 107.230 9.140 ;
  END
  END d1[3]
  PIN d1[4]
  USE SIGNAL ;
  DIRECTION INPUT ;
  ANTENNAGATEAREA 0.492800 ;
  PORT
      LAYER Metal3 ;
      RECT 129.510 0.000 129.790 9.140 ;
  END
  END d1[4]
  PIN d1[5]
  USE SIGNAL ;
  DIRECTION INPUT ;
  ANTENNAGATEAREA 0.492800 ;
  PORT
      LAYER Metal3 ;
      RECT 152.070 0.000 152.350 9.140 ;
  END
  END d1[5]
  PIN d1[6]
  USE SIGNAL ;
  DIRECTION INPUT ;
  ANTENNAGATEAREA 0.492800 ;
  PORT
      LAYER Metal3 ;
      RECT 174.630 0.000 174.910 9.140 ;
  END
  END d1[6]
  PIN d1[7]
  USE SIGNAL ;
  DIRECTION INPUT ;
  ANTENNAGATEAREA 0.492800 ;
  PORT
      LAYER Metal3 ;
      RECT 197.190 0.000 197.470 9.140 ;
  END
  END d1[7]
  PIN we1[0]
  USE SIGNAL ;
  DIRECTION INPUT ;
  ANTENNAGATEAREA 0.492800 ;
  PORT
      LAYER Metal3 ;
      RECT 206.070 0.000 206.350 1.000 ;
  END
  END we1[0]
  PIN q1[0]
  USE SIGNAL ;
  DIRECTION OUTPUT ;
  PORT
      LAYER Metal3 ;
      RECT 40.730 0.000 41.010 14.190 ;
  END
  END q1[0]
  PIN q1[1]
  USE SIGNAL ;
  DIRECTION OUTPUT ;
  PORT
      LAYER Metal3 ;
      RECT 63.290 0.000 63.570 14.190 ;
  END
  END q1[1]
  PIN q1[2]
  USE SIGNAL ;
  DIRECTION OUTPUT ;
  PORT
      LAYER Metal3 ;
      RECT 85.850 0.000 86.130 14.190 ;
  END
  END q1[2]
  PIN q1[3]
  USE SIGNAL ;
  DIRECTION OUTPUT ;
  PORT
      LAYER Metal3 ;
      RECT 108.410 0.000 108.690 14.190 ;
  END
  END q1[3]
  PIN q1[4]
  USE SIGNAL ;
  DIRECTION OUTPUT ;
  PORT
      LAYER Metal3 ;
      RECT 130.970 0.000 131.250 14.190 ;
  END
  END q1[4]
  PIN q1[5]
  USE SIGNAL ;
  DIRECTION OUTPUT ;
  PORT
      LAYER Metal3 ;
      RECT 153.530 0.000 153.810 14.190 ;
  END
  END q1[5]
  PIN q1[6]
  USE SIGNAL ;
  DIRECTION OUTPUT ;
  PORT
      LAYER Metal3 ;
      RECT 176.090 0.000 176.370 14.190 ;
  END
  END q1[6]
  PIN q1[7]
  USE SIGNAL ;
  DIRECTION OUTPUT ;
  PORT
      LAYER Metal3 ;
      RECT 198.650 0.000 198.930 14.190 ;
  END
  END q1[7]
  PIN a2[0]
  USE SIGNAL ;
  DIRECTION INPUT ;
  ANTENNAGATEAREA 0.492800 ;
  PORT
      LAYER Metal3 ;
      RECT 251.180 97.750 254.160 98.030 ;
  END
  END a2[0]
  PIN a2[1]
  USE SIGNAL ;
  DIRECTION INPUT ;
  ANTENNAGATEAREA 0.492800 ;
  PORT
      LAYER Metal3 ;
      RECT 251.180 92.610 254.160 92.890 ;
  END
  END a2[1]
  PIN a2[2]
  USE SIGNAL ;
  DIRECTION INPUT ;
  ANTENNAGATEAREA 0.492800 ;
  PORT
      LAYER Metal3 ;
      RECT 251.650 81.210 254.160 81.490 ;
  END
  END a2[2]
  PIN a2[3]
  USE SIGNAL ;
  DIRECTION INPUT ;
  ANTENNAGATEAREA 0.492800 ;
  PORT
      LAYER Metal3 ;
      RECT 251.650 68.290 254.160 68.570 ;
  END
  END a2[3]
  PIN a2[4]
  USE SIGNAL ;
  DIRECTION INPUT ;
  ANTENNAGATEAREA 0.492800 ;
  PORT
      LAYER Metal3 ;
      RECT 251.650 55.370 254.160 55.650 ;
  END
  END a2[4]
  PIN a2[5]
  USE SIGNAL ;
  DIRECTION INPUT ;
  ANTENNAGATEAREA 0.492800 ;
  PORT
      LAYER Metal3 ;
      RECT 251.650 42.450 254.160 42.730 ;
  END
  END a2[5]
  PIN a2[6]
  USE SIGNAL ;
  DIRECTION INPUT ;
  ANTENNAGATEAREA 0.492800 ;
  PORT
      LAYER Metal3 ;
      RECT 251.650 29.530 254.160 29.810 ;
  END
  END a2[6]
  PIN d2[0]
  USE SIGNAL ;
  DIRECTION INPUT ;
  ANTENNAGATEAREA 0.492800 ;
  PORT
      LAYER Metal3 ;
      RECT 56.690 103.420 56.970 112.560 ;
  END
  END d2[0]
  PIN d2[1]
  USE SIGNAL ;
  DIRECTION INPUT ;
  ANTENNAGATEAREA 0.492800 ;
  PORT
      LAYER Metal3 ;
      RECT 79.250 103.420 79.530 112.560 ;
  END
  END d2[1]
  PIN d2[2]
  USE SIGNAL ;
  DIRECTION INPUT ;
  ANTENNAGATEAREA 0.492800 ;
  PORT
      LAYER Metal3 ;
      RECT 101.810 103.420 102.090 112.560 ;
  END
  END d2[2]
  PIN d2[3]
  USE SIGNAL ;
  DIRECTION INPUT ;
  ANTENNAGATEAREA 0.492800 ;
  PORT
      LAYER Metal3 ;
      RECT 124.370 103.420 124.650 112.560 ;
  END
  END d2[3]
  PIN d2[4]
  USE SIGNAL ;
  DIRECTION INPUT ;
  ANTENNAGATEAREA 0.492800 ;
  PORT
      LAYER Metal3 ;
      RECT 146.930 103.420 147.210 112.560 ;
  END
  END d2[4]
  PIN d2[5]
  USE SIGNAL ;
  DIRECTION INPUT ;
  ANTENNAGATEAREA 0.492800 ;
  PORT
      LAYER Metal3 ;
      RECT 169.490 103.420 169.770 112.560 ;
  END
  END d2[5]
  PIN d2[6]
  USE SIGNAL ;
  DIRECTION INPUT ;
  ANTENNAGATEAREA 0.492800 ;
  PORT
      LAYER Metal3 ;
      RECT 192.050 103.420 192.330 112.560 ;
  END
  END d2[6]
  PIN d2[7]
  USE SIGNAL ;
  DIRECTION INPUT ;
  ANTENNAGATEAREA 0.492800 ;
  PORT
      LAYER Metal3 ;
      RECT 214.610 103.420 214.890 112.560 ;
  END
  END d2[7]
  PIN we2[0]
  USE SIGNAL ;
  DIRECTION INPUT ;
  ANTENNAGATEAREA 0.492800 ;
  PORT
      LAYER Metal3 ;
      RECT 47.810 111.560 48.090 112.560 ;
  END
  END we2[0]
  PIN q2[0]
  USE SIGNAL ;
  DIRECTION OUTPUT ;
  PORT
      LAYER Metal3 ;
      RECT 55.230 98.370 55.510 112.560 ;
  END
  END q2[0]
  PIN q2[1]
  USE SIGNAL ;
  DIRECTION OUTPUT ;
  PORT
      LAYER Metal3 ;
      RECT 77.790 98.370 78.070 112.560 ;
  END
  END q2[1]
  PIN q2[2]
  USE SIGNAL ;
  DIRECTION OUTPUT ;
  PORT
      LAYER Metal3 ;
      RECT 100.350 98.370 100.630 112.560 ;
  END
  END q2[2]
  PIN q2[3]
  USE SIGNAL ;
  DIRECTION OUTPUT ;
  PORT
      LAYER Metal3 ;
      RECT 122.910 98.370 123.190 112.560 ;
  END
  END q2[3]
  PIN q2[4]
  USE SIGNAL ;
  DIRECTION OUTPUT ;
  PORT
      LAYER Metal3 ;
      RECT 145.470 98.370 145.750 112.560 ;
  END
  END q2[4]
  PIN q2[5]
  USE SIGNAL ;
  DIRECTION OUTPUT ;
  PORT
      LAYER Metal3 ;
      RECT 168.030 98.370 168.310 112.560 ;
  END
  END q2[5]
  PIN q2[6]
  USE SIGNAL ;
  DIRECTION OUTPUT ;
  PORT
      LAYER Metal3 ;
      RECT 190.590 98.370 190.870 112.560 ;
  END
  END q2[6]
  PIN q2[7]
  USE SIGNAL ;
  DIRECTION OUTPUT ;
  PORT
      LAYER Metal3 ;
      RECT 213.150 98.370 213.430 112.560 ;
  END
  END q2[7]
  PIN vss
    USE GROUND ;
    DIRECTION INOUT ;
    PORT
      LAYER Metal3 ;
        RECT 36.840 18.780 217.320 19.780 ;
    END
    PORT
      LAYER Metal3 ;
        RECT 36.840 28.780 217.320 29.180 ;
    END
    PORT
      LAYER Metal3 ;
        RECT 36.840 22.995 217.320 23.275 ;
    END
    PORT
      LAYER Metal3 ;
        RECT 36.840 82.700 217.320 83.100 ;
    END
    PORT
      LAYER Metal3 ;
        RECT 36.840 55.740 217.320 56.140 ;
    END
    PORT
      LAYER Metal3 ;
        RECT 36.840 92.780 217.320 93.780 ;
    END
    PORT
      LAYER Metal3 ;
        RECT 36.840 89.285 217.320 89.565 ;
    END
  END vss
  PIN vdd
    USE POWER ;
    DIRECTION INOUT ;
    PORT
      LAYER Metal3 ;
        RECT 36.840 56.420 217.320 56.820 ;
    END
    PORT
      LAYER Metal3 ;
        RECT 36.840 29.460 217.320 29.860 ;
    END
    PORT
      LAYER Metal3 ;
        RECT 36.840 91.500 217.320 92.500 ;
    END
    PORT
      LAYER Metal3 ;
        RECT 36.840 20.060 217.320 21.060 ;
    END
    PORT
      LAYER Metal3 ;
        RECT 36.840 84.990 217.510 85.270 ;
    END
    PORT
      LAYER Metal3 ;
        RECT 36.650 27.290 217.320 27.570 ;
    END
    PORT
      LAYER Metal3 ;
        RECT 36.840 83.380 217.320 83.780 ;
    END
  END vdd
  OBS
    LAYER Metal1 ;
      RECT 0.000 0.000 254.160 112.560 ;
    LAYER Metal2 ;
      RECT 0.000 0.000 254.160 112.560 ;
    LAYER Metal3 ;
      RECT 0.000 0.000 254.160 112.560 ;
  END
END DP8TRBlock_128x8

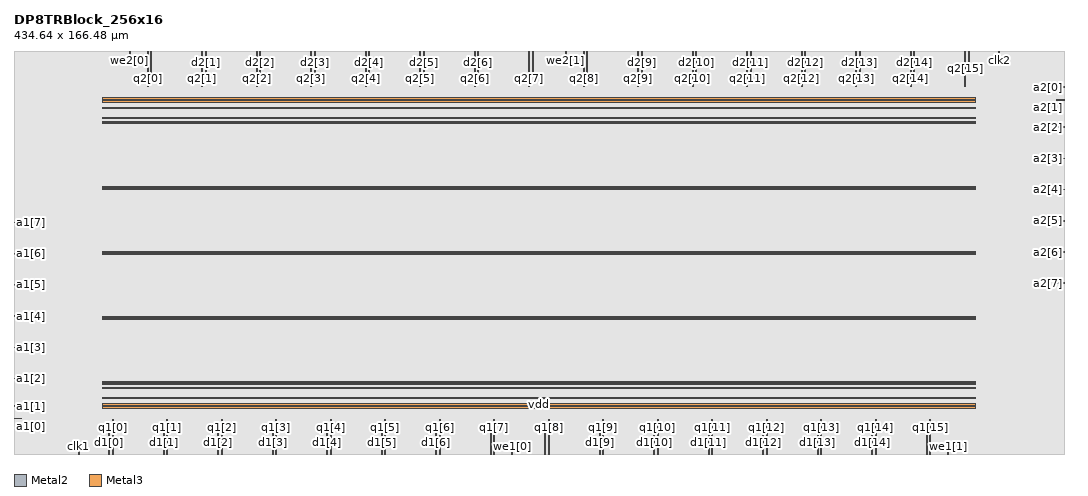
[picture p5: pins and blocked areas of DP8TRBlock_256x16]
MACRO DP8TRBlock_256x16
  CLASS BLOCK ;
  FOREIGN DP8TRBlock_256x16 ;
  ORIGIN 0.000 0.000 ;
  SIZE 434.640 BY 166.480 ;
  SYMMETRY X Y R90 ;
  PIN clk1
  USE CLOCK ;
  DIRECTION INPUT ;
  ANTENNAGATEAREA 0.492800 ;
  PORT
      LAYER Metal2 ;
      RECT 26.655 0.000 27.035 1.900 ;
  END
  END clk1
  PIN clk2
  USE CLOCK ;
  DIRECTION INPUT ;
  ANTENNAGATEAREA 0.492800 ;
  PORT
      LAYER Metal2 ;
      RECT 407.605 164.580 407.985 166.480 ;
  END
  END clk2
  PIN a1[0]
  USE SIGNAL ;
  DIRECTION INPUT ;
  ANTENNAGATEAREA 0.492800 ;
  PORT
      LAYER Metal3 ;
      RECT 0.000 14.530 2.980 14.810 ;
  END
  END a1[0]
  PIN a1[1]
  USE SIGNAL ;
  DIRECTION INPUT ;
  ANTENNAGATEAREA 0.492800 ;
  PORT
      LAYER Metal3 ;
      RECT 0.000 19.670 2.980 19.950 ;
  END
  END a1[1]
  PIN a1[2]
  USE SIGNAL ;
  DIRECTION INPUT ;
  ANTENNAGATEAREA 0.492800 ;
  PORT
      LAYER Metal3 ;
      RECT 0.000 31.070 2.510 31.350 ;
  END
  END a1[2]
  PIN a1[3]
  USE SIGNAL ;
  DIRECTION INPUT ;
  ANTENNAGATEAREA 0.492800 ;
  PORT
      LAYER Metal3 ;
      RECT 0.000 43.990 2.510 44.270 ;
  END
  END a1[3]
  PIN a1[4]
  USE SIGNAL ;
  DIRECTION INPUT ;
  ANTENNAGATEAREA 0.492800 ;
  PORT
      LAYER Metal3 ;
      RECT 0.000 56.910 2.510 57.190 ;
  END
  END a1[4]
  PIN a1[5]
  USE SIGNAL ;
  DIRECTION INPUT ;
  ANTENNAGATEAREA 0.492800 ;
  PORT
      LAYER Metal3 ;
      RECT 0.000 69.830 2.510 70.110 ;
  END
  END a1[5]
  PIN a1[6]
  USE SIGNAL ;
  DIRECTION INPUT ;
  ANTENNAGATEAREA 0.492800 ;
  PORT
      LAYER Metal3 ;
      RECT 0.000 82.750 2.510 83.030 ;
  END
  END a1[6]
  PIN a1[7]
  USE SIGNAL ;
  DIRECTION INPUT ;
  ANTENNAGATEAREA 0.492800 ;
  PORT
      LAYER Metal3 ;
      RECT 0.000 95.670 2.510 95.950 ;
  END
  END a1[7]
  PIN d1[0]
  USE SIGNAL ;
  DIRECTION INPUT ;
  ANTENNAGATEAREA 0.492800 ;
  PORT
      LAYER Metal3 ;
      RECT 39.270 0.000 39.550 9.140 ;
  END
  END d1[0]
  PIN d1[1]
  USE SIGNAL ;
  DIRECTION INPUT ;
  ANTENNAGATEAREA 0.492800 ;
  PORT
      LAYER Metal3 ;
      RECT 61.830 0.000 62.110 9.140 ;
  END
  END d1[1]
  PIN d1[2]
  USE SIGNAL ;
  DIRECTION INPUT ;
  ANTENNAGATEAREA 0.492800 ;
  PORT
      LAYER Metal3 ;
      RECT 84.390 0.000 84.670 9.140 ;
  END
  END d1[2]
  PIN d1[3]
  USE SIGNAL ;
  DIRECTION INPUT ;
  ANTENNAGATEAREA 0.492800 ;
  PORT
      LAYER Metal3 ;
      RECT 106.950 0.000 107.230 9.140 ;
  END
  END d1[3]
  PIN d1[4]
  USE SIGNAL ;
  DIRECTION INPUT ;
  ANTENNAGATEAREA 0.492800 ;
  PORT
      LAYER Metal3 ;
      RECT 129.510 0.000 129.790 9.140 ;
  END
  END d1[4]
  PIN d1[5]
  USE SIGNAL ;
  DIRECTION INPUT ;
  ANTENNAGATEAREA 0.492800 ;
  PORT
      LAYER Metal3 ;
      RECT 152.070 0.000 152.350 9.140 ;
  END
  END d1[5]
  PIN d1[6]
  USE SIGNAL ;
  DIRECTION INPUT ;
  ANTENNAGATEAREA 0.492800 ;
  PORT
      LAYER Metal3 ;
      RECT 174.630 0.000 174.910 9.140 ;
  END
  END d1[6]
  PIN d1[7]
  USE SIGNAL ;
  DIRECTION INPUT ;
  ANTENNAGATEAREA 0.492800 ;
  PORT
      LAYER Metal3 ;
      RECT 197.190 0.000 197.470 9.140 ;
  END
  END d1[7]
  PIN d1[8]
  USE SIGNAL ;
  DIRECTION INPUT ;
  ANTENNAGATEAREA 0.492800 ;
  PORT
      LAYER Metal3 ;
      RECT 219.750 0.000 220.030 9.140 ;
  END
  END d1[8]
  PIN d1[9]
  USE SIGNAL ;
  DIRECTION INPUT ;
  ANTENNAGATEAREA 0.492800 ;
  PORT
      LAYER Metal3 ;
      RECT 242.310 0.000 242.590 9.140 ;
  END
  END d1[9]
  PIN d1[10]
  USE SIGNAL ;
  DIRECTION INPUT ;
  ANTENNAGATEAREA 0.492800 ;
  PORT
      LAYER Metal3 ;
      RECT 264.870 0.000 265.150 9.140 ;
  END
  END d1[10]
  PIN d1[11]
  USE SIGNAL ;
  DIRECTION INPUT ;
  ANTENNAGATEAREA 0.492800 ;
  PORT
      LAYER Metal3 ;
      RECT 287.430 0.000 287.710 9.140 ;
  END
  END d1[11]
  PIN d1[12]
  USE SIGNAL ;
  DIRECTION INPUT ;
  ANTENNAGATEAREA 0.492800 ;
  PORT
      LAYER Metal3 ;
      RECT 309.990 0.000 310.270 9.140 ;
  END
  END d1[12]
  PIN d1[13]
  USE SIGNAL ;
  DIRECTION INPUT ;
  ANTENNAGATEAREA 0.492800 ;
  PORT
      LAYER Metal3 ;
      RECT 332.550 0.000 332.830 9.140 ;
  END
  END d1[13]
  PIN d1[14]
  USE SIGNAL ;
  DIRECTION INPUT ;
  ANTENNAGATEAREA 0.492800 ;
  PORT
      LAYER Metal3 ;
      RECT 355.110 0.000 355.390 9.140 ;
  END
  END d1[14]
  PIN d1[15]
  USE SIGNAL ;
  DIRECTION INPUT ;
  ANTENNAGATEAREA 0.492800 ;
  PORT
      LAYER Metal3 ;
      RECT 377.670 0.000 377.950 9.140 ;
  END
  END d1[15]
  PIN we1[0]
  USE SIGNAL ;
  DIRECTION INPUT ;
  ANTENNAGATEAREA 0.492800 ;
  PORT
      LAYER Metal3 ;
      RECT 206.070 0.000 206.350 1.000 ;
  END
  END we1[0]
  PIN we1[1]
  USE SIGNAL ;
  DIRECTION INPUT ;
  ANTENNAGATEAREA 0.492800 ;
  PORT
      LAYER Metal3 ;
      RECT 386.550 0.000 386.830 1.000 ;
  END
  END we1[1]
  PIN q1[0]
  USE SIGNAL ;
  DIRECTION OUTPUT ;
  PORT
      LAYER Metal3 ;
      RECT 40.730 0.000 41.010 14.190 ;
  END
  END q1[0]
  PIN q1[1]
  USE SIGNAL ;
  DIRECTION OUTPUT ;
  PORT
      LAYER Metal3 ;
      RECT 63.290 0.000 63.570 14.190 ;
  END
  END q1[1]
  PIN q1[2]
  USE SIGNAL ;
  DIRECTION OUTPUT ;
  PORT
      LAYER Metal3 ;
      RECT 85.850 0.000 86.130 14.190 ;
  END
  END q1[2]
  PIN q1[3]
  USE SIGNAL ;
  DIRECTION OUTPUT ;
  PORT
      LAYER Metal3 ;
      RECT 108.410 0.000 108.690 14.190 ;
  END
  END q1[3]
  PIN q1[4]
  USE SIGNAL ;
  DIRECTION OUTPUT ;
  PORT
      LAYER Metal3 ;
      RECT 130.970 0.000 131.250 14.190 ;
  END
  END q1[4]
  PIN q1[5]
  USE SIGNAL ;
  DIRECTION OUTPUT ;
  PORT
      LAYER Metal3 ;
      RECT 153.530 0.000 153.810 14.190 ;
  END
  END q1[5]
  PIN q1[6]
  USE SIGNAL ;
  DIRECTION OUTPUT ;
  PORT
      LAYER Metal3 ;
      RECT 176.090 0.000 176.370 14.190 ;
  END
  END q1[6]
  PIN q1[7]
  USE SIGNAL ;
  DIRECTION OUTPUT ;
  PORT
      LAYER Metal3 ;
      RECT 198.650 0.000 198.930 14.190 ;
  END
  END q1[7]
  PIN q1[8]
  USE SIGNAL ;
  DIRECTION OUTPUT ;
  PORT
      LAYER Metal3 ;
      RECT 221.210 0.000 221.490 14.190 ;
  END
  END q1[8]
  PIN q1[9]
  USE SIGNAL ;
  DIRECTION OUTPUT ;
  PORT
      LAYER Metal3 ;
      RECT 243.770 0.000 244.050 14.190 ;
  END
  END q1[9]
  PIN q1[10]
  USE SIGNAL ;
  DIRECTION OUTPUT ;
  PORT
      LAYER Metal3 ;
      RECT 266.330 0.000 266.610 14.190 ;
  END
  END q1[10]
  PIN q1[11]
  USE SIGNAL ;
  DIRECTION OUTPUT ;
  PORT
      LAYER Metal3 ;
      RECT 288.890 0.000 289.170 14.190 ;
  END
  END q1[11]
  PIN q1[12]
  USE SIGNAL ;
  DIRECTION OUTPUT ;
  PORT
      LAYER Metal3 ;
      RECT 311.450 0.000 311.730 14.190 ;
  END
  END q1[12]
  PIN q1[13]
  USE SIGNAL ;
  DIRECTION OUTPUT ;
  PORT
      LAYER Metal3 ;
      RECT 334.010 0.000 334.290 14.190 ;
  END
  END q1[13]
  PIN q1[14]
  USE SIGNAL ;
  DIRECTION OUTPUT ;
  PORT
      LAYER Metal3 ;
      RECT 356.570 0.000 356.850 14.190 ;
  END
  END q1[14]
  PIN q1[15]
  USE SIGNAL ;
  DIRECTION OUTPUT ;
  PORT
      LAYER Metal3 ;
      RECT 379.130 0.000 379.410 14.190 ;
  END
  END q1[15]
  PIN a2[0]
  USE SIGNAL ;
  DIRECTION INPUT ;
  ANTENNAGATEAREA 0.492800 ;
  PORT
      LAYER Metal3 ;
      RECT 431.660 151.670 434.640 151.950 ;
  END
  END a2[0]
  PIN a2[1]
  USE SIGNAL ;
  DIRECTION INPUT ;
  ANTENNAGATEAREA 0.492800 ;
  PORT
      LAYER Metal3 ;
      RECT 431.660 146.530 434.640 146.810 ;
  END
  END a2[1]
  PIN a2[2]
  USE SIGNAL ;
  DIRECTION INPUT ;
  ANTENNAGATEAREA 0.492800 ;
  PORT
      LAYER Metal3 ;
      RECT 432.130 135.130 434.640 135.410 ;
  END
  END a2[2]
  PIN a2[3]
  USE SIGNAL ;
  DIRECTION INPUT ;
  ANTENNAGATEAREA 0.492800 ;
  PORT
      LAYER Metal3 ;
      RECT 432.130 122.210 434.640 122.490 ;
  END
  END a2[3]
  PIN a2[4]
  USE SIGNAL ;
  DIRECTION INPUT ;
  ANTENNAGATEAREA 0.492800 ;
  PORT
      LAYER Metal3 ;
      RECT 432.130 109.290 434.640 109.570 ;
  END
  END a2[4]
  PIN a2[5]
  USE SIGNAL ;
  DIRECTION INPUT ;
  ANTENNAGATEAREA 0.492800 ;
  PORT
      LAYER Metal3 ;
      RECT 432.130 96.370 434.640 96.650 ;
  END
  END a2[5]
  PIN a2[6]
  USE SIGNAL ;
  DIRECTION INPUT ;
  ANTENNAGATEAREA 0.492800 ;
  PORT
      LAYER Metal3 ;
      RECT 432.130 83.450 434.640 83.730 ;
  END
  END a2[6]
  PIN a2[7]
  USE SIGNAL ;
  DIRECTION INPUT ;
  ANTENNAGATEAREA 0.492800 ;
  PORT
      LAYER Metal3 ;
      RECT 432.130 70.530 434.640 70.810 ;
  END
  END a2[7]
  PIN d2[0]
  USE SIGNAL ;
  DIRECTION INPUT ;
  ANTENNAGATEAREA 0.492800 ;
  PORT
      LAYER Metal3 ;
      RECT 56.690 157.340 56.970 166.480 ;
  END
  END d2[0]
  PIN d2[1]
  USE SIGNAL ;
  DIRECTION INPUT ;
  ANTENNAGATEAREA 0.492800 ;
  PORT
      LAYER Metal3 ;
      RECT 79.250 157.340 79.530 166.480 ;
  END
  END d2[1]
  PIN d2[2]
  USE SIGNAL ;
  DIRECTION INPUT ;
  ANTENNAGATEAREA 0.492800 ;
  PORT
      LAYER Metal3 ;
      RECT 101.810 157.340 102.090 166.480 ;
  END
  END d2[2]
  PIN d2[3]
  USE SIGNAL ;
  DIRECTION INPUT ;
  ANTENNAGATEAREA 0.492800 ;
  PORT
      LAYER Metal3 ;
      RECT 124.370 157.340 124.650 166.480 ;
  END
  END d2[3]
  PIN d2[4]
  USE SIGNAL ;
  DIRECTION INPUT ;
  ANTENNAGATEAREA 0.492800 ;
  PORT
      LAYER Metal3 ;
      RECT 146.930 157.340 147.210 166.480 ;
  END
  END d2[4]
  PIN d2[5]
  USE SIGNAL ;
  DIRECTION INPUT ;
  ANTENNAGATEAREA 0.492800 ;
  PORT
      LAYER Metal3 ;
      RECT 169.490 157.340 169.770 166.480 ;
  END
  END d2[5]
  PIN d2[6]
  USE SIGNAL ;
  DIRECTION INPUT ;
  ANTENNAGATEAREA 0.492800 ;
  PORT
      LAYER Metal3 ;
      RECT 192.050 157.340 192.330 166.480 ;
  END
  END d2[6]
  PIN d2[7]
  USE SIGNAL ;
  DIRECTION INPUT ;
  ANTENNAGATEAREA 0.492800 ;
  PORT
      LAYER Metal3 ;
      RECT 214.610 157.340 214.890 166.480 ;
  END
  END d2[7]
  PIN d2[8]
  USE SIGNAL ;
  DIRECTION INPUT ;
  ANTENNAGATEAREA 0.492800 ;
  PORT
      LAYER Metal3 ;
      RECT 237.170 157.340 237.450 166.480 ;
  END
  END d2[8]
  PIN d2[9]
  USE SIGNAL ;
  DIRECTION INPUT ;
  ANTENNAGATEAREA 0.492800 ;
  PORT
      LAYER Metal3 ;
      RECT 259.730 157.340 260.010 166.480 ;
  END
  END d2[9]
  PIN d2[10]
  USE SIGNAL ;
  DIRECTION INPUT ;
  ANTENNAGATEAREA 0.492800 ;
  PORT
      LAYER Metal3 ;
      RECT 282.290 157.340 282.570 166.480 ;
  END
  END d2[10]
  PIN d2[11]
  USE SIGNAL ;
  DIRECTION INPUT ;
  ANTENNAGATEAREA 0.492800 ;
  PORT
      LAYER Metal3 ;
      RECT 304.850 157.340 305.130 166.480 ;
  END
  END d2[11]
  PIN d2[12]
  USE SIGNAL ;
  DIRECTION INPUT ;
  ANTENNAGATEAREA 0.492800 ;
  PORT
      LAYER Metal3 ;
      RECT 327.410 157.340 327.690 166.480 ;
  END
  END d2[12]
  PIN d2[13]
  USE SIGNAL ;
  DIRECTION INPUT ;
  ANTENNAGATEAREA 0.492800 ;
  PORT
      LAYER Metal3 ;
      RECT 349.970 157.340 350.250 166.480 ;
  END
  END d2[13]
  PIN d2[14]
  USE SIGNAL ;
  DIRECTION INPUT ;
  ANTENNAGATEAREA 0.492800 ;
  PORT
      LAYER Metal3 ;
      RECT 372.530 157.340 372.810 166.480 ;
  END
  END d2[14]
  PIN d2[15]
  USE SIGNAL ;
  DIRECTION INPUT ;
  ANTENNAGATEAREA 0.492800 ;
  PORT
      LAYER Metal3 ;
      RECT 395.090 157.340 395.370 166.480 ;
  END
  END d2[15]
  PIN we2[0]
  USE SIGNAL ;
  DIRECTION INPUT ;
  ANTENNAGATEAREA 0.492800 ;
  PORT
      LAYER Metal3 ;
      RECT 47.810 165.480 48.090 166.480 ;
  END
  END we2[0]
  PIN we2[1]
  USE SIGNAL ;
  DIRECTION INPUT ;
  ANTENNAGATEAREA 0.492800 ;
  PORT
      LAYER Metal3 ;
      RECT 228.290 165.480 228.570 166.480 ;
  END
  END we2[1]
  PIN q2[0]
  USE SIGNAL ;
  DIRECTION OUTPUT ;
  PORT
      LAYER Metal3 ;
      RECT 55.230 152.290 55.510 166.480 ;
  END
  END q2[0]
  PIN q2[1]
  USE SIGNAL ;
  DIRECTION OUTPUT ;
  PORT
      LAYER Metal3 ;
      RECT 77.790 152.290 78.070 166.480 ;
  END
  END q2[1]
  PIN q2[2]
  USE SIGNAL ;
  DIRECTION OUTPUT ;
  PORT
      LAYER Metal3 ;
      RECT 100.350 152.290 100.630 166.480 ;
  END
  END q2[2]
  PIN q2[3]
  USE SIGNAL ;
  DIRECTION OUTPUT ;
  PORT
      LAYER Metal3 ;
      RECT 122.910 152.290 123.190 166.480 ;
  END
  END q2[3]
  PIN q2[4]
  USE SIGNAL ;
  DIRECTION OUTPUT ;
  PORT
      LAYER Metal3 ;
      RECT 145.470 152.290 145.750 166.480 ;
  END
  END q2[4]
  PIN q2[5]
  USE SIGNAL ;
  DIRECTION OUTPUT ;
  PORT
      LAYER Metal3 ;
      RECT 168.030 152.290 168.310 166.480 ;
  END
  END q2[5]
  PIN q2[6]
  USE SIGNAL ;
  DIRECTION OUTPUT ;
  PORT
      LAYER Metal3 ;
      RECT 190.590 152.290 190.870 166.480 ;
  END
  END q2[6]
  PIN q2[7]
  USE SIGNAL ;
  DIRECTION OUTPUT ;
  PORT
      LAYER Metal3 ;
      RECT 213.150 152.290 213.430 166.480 ;
  END
  END q2[7]
  PIN q2[8]
  USE SIGNAL ;
  DIRECTION OUTPUT ;
  PORT
      LAYER Metal3 ;
      RECT 235.710 152.290 235.990 166.480 ;
  END
  END q2[8]
  PIN q2[9]
  USE SIGNAL ;
  DIRECTION OUTPUT ;
  PORT
      LAYER Metal3 ;
      RECT 258.270 152.290 258.550 166.480 ;
  END
  END q2[9]
  PIN q2[10]
  USE SIGNAL ;
  DIRECTION OUTPUT ;
  PORT
      LAYER Metal3 ;
      RECT 280.830 152.290 281.110 166.480 ;
  END
  END q2[10]
  PIN q2[11]
  USE SIGNAL ;
  DIRECTION OUTPUT ;
  PORT
      LAYER Metal3 ;
      RECT 303.390 152.290 303.670 166.480 ;
  END
  END q2[11]
  PIN q2[12]
  USE SIGNAL ;
  DIRECTION OUTPUT ;
  PORT
      LAYER Metal3 ;
      RECT 325.950 152.290 326.230 166.480 ;
  END
  END q2[12]
  PIN q2[13]
  USE SIGNAL ;
  DIRECTION OUTPUT ;
  PORT
      LAYER Metal3 ;
      RECT 348.510 152.290 348.790 166.480 ;
  END
  END q2[13]
  PIN q2[14]
  USE SIGNAL ;
  DIRECTION OUTPUT ;
  PORT
      LAYER Metal3 ;
      RECT 371.070 152.290 371.350 166.480 ;
  END
  END q2[14]
  PIN q2[15]
  USE SIGNAL ;
  DIRECTION OUTPUT ;
  PORT
      LAYER Metal3 ;
      RECT 393.630 152.290 393.910 166.480 ;
  END
  END q2[15]
  PIN vss
    USE GROUND ;
    DIRECTION INOUT ;
    PORT
      LAYER Metal3 ;
        RECT 36.840 109.660 397.800 110.060 ;
    END
    PORT
      LAYER Metal3 ;
        RECT 36.840 22.995 397.800 23.275 ;
    END
    PORT
      LAYER Metal3 ;
        RECT 36.840 55.740 397.800 56.140 ;
    END
    PORT
      LAYER Metal3 ;
        RECT 36.840 136.620 397.800 137.020 ;
    END
    PORT
      LAYER Metal3 ;
        RECT 36.840 18.780 397.800 19.780 ;
    END
    PORT
      LAYER Metal3 ;
        RECT 36.840 82.700 397.800 83.100 ;
    END
    PORT
      LAYER Metal3 ;
        RECT 36.840 143.205 397.800 143.485 ;
    END
    PORT
      LAYER Metal3 ;
        RECT 36.840 28.780 397.800 29.180 ;
    END
    PORT
      LAYER Metal3 ;
        RECT 36.840 146.700 397.800 147.700 ;
    END
  END vss
  PIN vdd
    USE POWER ;
    DIRECTION INOUT ;
    PORT
      LAYER Metal3 ;
        RECT 36.840 29.460 397.800 29.860 ;
    END
    PORT
      LAYER Metal3 ;
        RECT 36.840 20.060 397.800 21.060 ;
    END
    PORT
      LAYER Metal3 ;
        RECT 36.840 56.420 397.800 56.820 ;
    END
    PORT
      LAYER Metal3 ;
        RECT 36.840 145.420 397.800 146.420 ;
    END
    PORT
      LAYER Metal3 ;
        RECT 36.650 27.290 397.800 27.570 ;
    END
    PORT
      LAYER Metal3 ;
        RECT 36.840 110.340 397.800 110.740 ;
    END
    PORT
      LAYER Metal3 ;
        RECT 36.840 137.300 397.800 137.700 ;
    END
    PORT
      LAYER Metal3 ;
        RECT 36.840 138.910 397.990 139.190 ;
    END
    PORT
      LAYER Metal3 ;
        RECT 36.840 83.380 397.800 83.780 ;
    END
  END vdd
  OBS
    LAYER Metal1 ;
      RECT 0.000 0.000 434.640 166.480 ;
    LAYER Metal2 ;
      RECT 0.000 0.000 434.640 166.480 ;
    LAYER Metal3 ;
      RECT 0.000 0.000 434.640 166.480 ;
  END
END DP8TRBlock_256x16

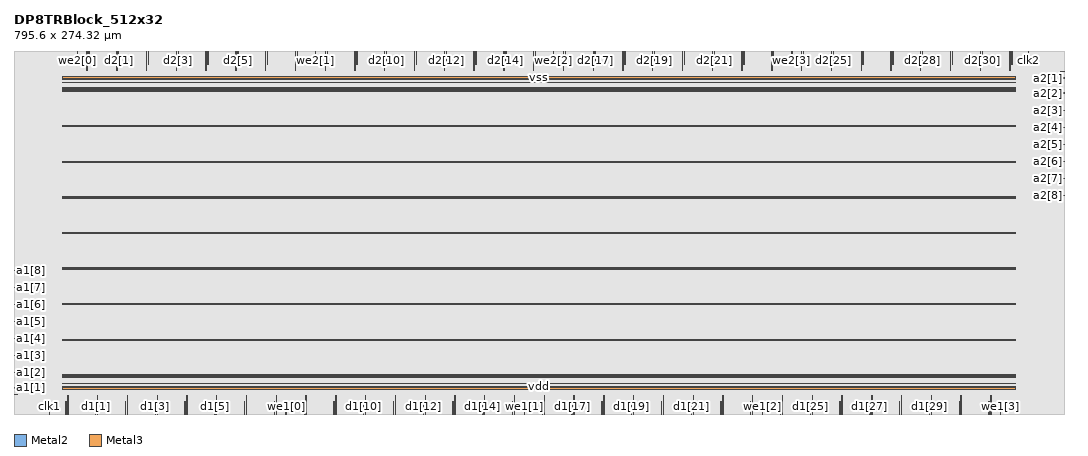
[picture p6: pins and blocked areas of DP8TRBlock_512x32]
MACRO DP8TRBlock_512x32
  CLASS BLOCK ;
  FOREIGN DP8TRBlock_512x32 ;
  ORIGIN 0.000 0.000 ;
  SIZE 795.600 BY 274.320 ;
  SYMMETRY X Y R90 ;
  PIN clk1
  USE CLOCK ;
  DIRECTION INPUT ;
  ANTENNAGATEAREA 0.492800 ;
  PORT
      LAYER Metal2 ;
      RECT 26.655 0.000 27.035 1.900 ;
  END
  END clk1
  PIN clk2
  USE CLOCK ;
  DIRECTION INPUT ;
  ANTENNAGATEAREA 0.492800 ;
  PORT
      LAYER Metal2 ;
      RECT 768.565 272.420 768.945 274.320 ;
  END
  END clk2
  PIN a1[0]
  USE SIGNAL ;
  DIRECTION INPUT ;
  ANTENNAGATEAREA 0.492800 ;
  PORT
      LAYER Metal3 ;
      RECT 0.000 14.530 2.980 14.810 ;
  END
  END a1[0]
  PIN a1[1]
  USE SIGNAL ;
  DIRECTION INPUT ;
  ANTENNAGATEAREA 0.492800 ;
  PORT
      LAYER Metal3 ;
      RECT 0.000 19.670 2.980 19.950 ;
  END
  END a1[1]
  PIN a1[2]
  USE SIGNAL ;
  DIRECTION INPUT ;
  ANTENNAGATEAREA 0.492800 ;
  PORT
      LAYER Metal3 ;
      RECT 0.000 31.070 2.510 31.350 ;
  END
  END a1[2]
  PIN a1[3]
  USE SIGNAL ;
  DIRECTION INPUT ;
  ANTENNAGATEAREA 0.492800 ;
  PORT
      LAYER Metal3 ;
      RECT 0.000 43.990 2.510 44.270 ;
  END
  END a1[3]
  PIN a1[4]
  USE SIGNAL ;
  DIRECTION INPUT ;
  ANTENNAGATEAREA 0.492800 ;
  PORT
      LAYER Metal3 ;
      RECT 0.000 56.910 2.510 57.190 ;
  END
  END a1[4]
  PIN a1[5]
  USE SIGNAL ;
  DIRECTION INPUT ;
  ANTENNAGATEAREA 0.492800 ;
  PORT
      LAYER Metal3 ;
      RECT 0.000 69.830 2.510 70.110 ;
  END
  END a1[5]
  PIN a1[6]
  USE SIGNAL ;
  DIRECTION INPUT ;
  ANTENNAGATEAREA 0.492800 ;
  PORT
      LAYER Metal3 ;
      RECT 0.000 82.750 2.510 83.030 ;
  END
  END a1[6]
  PIN a1[7]
  USE SIGNAL ;
  DIRECTION INPUT ;
  ANTENNAGATEAREA 0.492800 ;
  PORT
      LAYER Metal3 ;
      RECT 0.000 95.670 2.510 95.950 ;
  END
  END a1[7]
  PIN a1[8]
  USE SIGNAL ;
  DIRECTION INPUT ;
  ANTENNAGATEAREA 0.492800 ;
  PORT
      LAYER Metal3 ;
      RECT 0.000 108.590 2.510 108.870 ;
  END
  END a1[8]
  PIN d1[0]
  USE SIGNAL ;
  DIRECTION INPUT ;
  ANTENNAGATEAREA 0.492800 ;
  PORT
      LAYER Metal3 ;
      RECT 39.270 0.000 39.550 9.140 ;
  END
  END d1[0]
  PIN d1[1]
  USE SIGNAL ;
  DIRECTION INPUT ;
  ANTENNAGATEAREA 0.492800 ;
  PORT
      LAYER Metal3 ;
      RECT 61.830 0.000 62.110 9.140 ;
  END
  END d1[1]
  PIN d1[2]
  USE SIGNAL ;
  DIRECTION INPUT ;
  ANTENNAGATEAREA 0.492800 ;
  PORT
      LAYER Metal3 ;
      RECT 84.390 0.000 84.670 9.140 ;
  END
  END d1[2]
  PIN d1[3]
  USE SIGNAL ;
  DIRECTION INPUT ;
  ANTENNAGATEAREA 0.492800 ;
  PORT
      LAYER Metal3 ;
      RECT 106.950 0.000 107.230 9.140 ;
  END
  END d1[3]
  PIN d1[4]
  USE SIGNAL ;
  DIRECTION INPUT ;
  ANTENNAGATEAREA 0.492800 ;
  PORT
      LAYER Metal3 ;
      RECT 129.510 0.000 129.790 9.140 ;
  END
  END d1[4]
  PIN d1[5]
  USE SIGNAL ;
  DIRECTION INPUT ;
  ANTENNAGATEAREA 0.492800 ;
  PORT
      LAYER Metal3 ;
      RECT 152.070 0.000 152.350 9.140 ;
  END
  END d1[5]
  PIN d1[6]
  USE SIGNAL ;
  DIRECTION INPUT ;
  ANTENNAGATEAREA 0.492800 ;
  PORT
      LAYER Metal3 ;
      RECT 174.630 0.000 174.910 9.140 ;
  END
  END d1[6]
  PIN d1[7]
  USE SIGNAL ;
  DIRECTION INPUT ;
  ANTENNAGATEAREA 0.492800 ;
  PORT
      LAYER Metal3 ;
      RECT 197.190 0.000 197.470 9.140 ;
  END
  END d1[7]
  PIN d1[8]
  USE SIGNAL ;
  DIRECTION INPUT ;
  ANTENNAGATEAREA 0.492800 ;
  PORT
      LAYER Metal3 ;
      RECT 219.750 0.000 220.030 9.140 ;
  END
  END d1[8]
  PIN d1[9]
  USE SIGNAL ;
  DIRECTION INPUT ;
  ANTENNAGATEAREA 0.492800 ;
  PORT
      LAYER Metal3 ;
      RECT 242.310 0.000 242.590 9.140 ;
  END
  END d1[9]
  PIN d1[10]
  USE SIGNAL ;
  DIRECTION INPUT ;
  ANTENNAGATEAREA 0.492800 ;
  PORT
      LAYER Metal3 ;
      RECT 264.870 0.000 265.150 9.140 ;
  END
  END d1[10]
  PIN d1[11]
  USE SIGNAL ;
  DIRECTION INPUT ;
  ANTENNAGATEAREA 0.492800 ;
  PORT
      LAYER Metal3 ;
      RECT 287.430 0.000 287.710 9.140 ;
  END
  END d1[11]
  PIN d1[12]
  USE SIGNAL ;
  DIRECTION INPUT ;
  ANTENNAGATEAREA 0.492800 ;
  PORT
      LAYER Metal3 ;
      RECT 309.990 0.000 310.270 9.140 ;
  END
  END d1[12]
  PIN d1[13]
  USE SIGNAL ;
  DIRECTION INPUT ;
  ANTENNAGATEAREA 0.492800 ;
  PORT
      LAYER Metal3 ;
      RECT 332.550 0.000 332.830 9.140 ;
  END
  END d1[13]
  PIN d1[14]
  USE SIGNAL ;
  DIRECTION INPUT ;
  ANTENNAGATEAREA 0.492800 ;
  PORT
      LAYER Metal3 ;
      RECT 355.110 0.000 355.390 9.140 ;
  END
  END d1[14]
  PIN d1[15]
  USE SIGNAL ;
  DIRECTION INPUT ;
  ANTENNAGATEAREA 0.492800 ;
  PORT
      LAYER Metal3 ;
      RECT 377.670 0.000 377.950 9.140 ;
  END
  END d1[15]
  PIN d1[16]
  USE SIGNAL ;
  DIRECTION INPUT ;
  ANTENNAGATEAREA 0.492800 ;
  PORT
      LAYER Metal3 ;
      RECT 400.230 0.000 400.510 9.140 ;
  END
  END d1[16]
  PIN d1[17]
  USE SIGNAL ;
  DIRECTION INPUT ;
  ANTENNAGATEAREA 0.492800 ;
  PORT
      LAYER Metal3 ;
      RECT 422.790 0.000 423.070 9.140 ;
  END
  END d1[17]
  PIN d1[18]
  USE SIGNAL ;
  DIRECTION INPUT ;
  ANTENNAGATEAREA 0.492800 ;
  PORT
      LAYER Metal3 ;
      RECT 445.350 0.000 445.630 9.140 ;
  END
  END d1[18]
  PIN d1[19]
  USE SIGNAL ;
  DIRECTION INPUT ;
  ANTENNAGATEAREA 0.492800 ;
  PORT
      LAYER Metal3 ;
      RECT 467.910 0.000 468.190 9.140 ;
  END
  END d1[19]
  PIN d1[20]
  USE SIGNAL ;
  DIRECTION INPUT ;
  ANTENNAGATEAREA 0.492800 ;
  PORT
      LAYER Metal3 ;
      RECT 490.470 0.000 490.750 9.140 ;
  END
  END d1[20]
  PIN d1[21]
  USE SIGNAL ;
  DIRECTION INPUT ;
  ANTENNAGATEAREA 0.492800 ;
  PORT
      LAYER Metal3 ;
      RECT 513.030 0.000 513.310 9.140 ;
  END
  END d1[21]
  PIN d1[22]
  USE SIGNAL ;
  DIRECTION INPUT ;
  ANTENNAGATEAREA 0.492800 ;
  PORT
      LAYER Metal3 ;
      RECT 535.590 0.000 535.870 9.140 ;
  END
  END d1[22]
  PIN d1[23]
  USE SIGNAL ;
  DIRECTION INPUT ;
  ANTENNAGATEAREA 0.492800 ;
  PORT
      LAYER Metal3 ;
      RECT 558.150 0.000 558.430 9.140 ;
  END
  END d1[23]
  PIN d1[24]
  USE SIGNAL ;
  DIRECTION INPUT ;
  ANTENNAGATEAREA 0.492800 ;
  PORT
      LAYER Metal3 ;
      RECT 580.710 0.000 580.990 9.140 ;
  END
  END d1[24]
  PIN d1[25]
  USE SIGNAL ;
  DIRECTION INPUT ;
  ANTENNAGATEAREA 0.492800 ;
  PORT
      LAYER Metal3 ;
      RECT 603.270 0.000 603.550 9.140 ;
  END
  END d1[25]
  PIN d1[26]
  USE SIGNAL ;
  DIRECTION INPUT ;
  ANTENNAGATEAREA 0.492800 ;
  PORT
      LAYER Metal3 ;
      RECT 625.830 0.000 626.110 9.140 ;
  END
  END d1[26]
  PIN d1[27]
  USE SIGNAL ;
  DIRECTION INPUT ;
  ANTENNAGATEAREA 0.492800 ;
  PORT
      LAYER Metal3 ;
      RECT 648.390 0.000 648.670 9.140 ;
  END
  END d1[27]
  PIN d1[28]
  USE SIGNAL ;
  DIRECTION INPUT ;
  ANTENNAGATEAREA 0.492800 ;
  PORT
      LAYER Metal3 ;
      RECT 670.950 0.000 671.230 9.140 ;
  END
  END d1[28]
  PIN d1[29]
  USE SIGNAL ;
  DIRECTION INPUT ;
  ANTENNAGATEAREA 0.492800 ;
  PORT
      LAYER Metal3 ;
      RECT 693.510 0.000 693.790 9.140 ;
  END
  END d1[29]
  PIN d1[30]
  USE SIGNAL ;
  DIRECTION INPUT ;
  ANTENNAGATEAREA 0.492800 ;
  PORT
      LAYER Metal3 ;
      RECT 716.070 0.000 716.350 9.140 ;
  END
  END d1[30]
  PIN d1[31]
  USE SIGNAL ;
  DIRECTION INPUT ;
  ANTENNAGATEAREA 0.492800 ;
  PORT
      LAYER Metal3 ;
      RECT 738.630 0.000 738.910 9.140 ;
  END
  END d1[31]
  PIN we1[0]
  USE SIGNAL ;
  DIRECTION INPUT ;
  ANTENNAGATEAREA 0.492800 ;
  PORT
      LAYER Metal3 ;
      RECT 206.070 0.000 206.350 1.000 ;
  END
  END we1[0]
  PIN we1[1]
  USE SIGNAL ;
  DIRECTION INPUT ;
  ANTENNAGATEAREA 0.492800 ;
  PORT
      LAYER Metal3 ;
      RECT 386.550 0.000 386.830 1.000 ;
  END
  END we1[1]
  PIN we1[2]
  USE SIGNAL ;
  DIRECTION INPUT ;
  ANTENNAGATEAREA 0.492800 ;
  PORT
      LAYER Metal3 ;
      RECT 567.030 0.000 567.310 1.000 ;
  END
  END we1[2]
  PIN we1[3]
  USE SIGNAL ;
  DIRECTION INPUT ;
  ANTENNAGATEAREA 0.492800 ;
  PORT
      LAYER Metal3 ;
      RECT 747.510 0.000 747.790 1.000 ;
  END
  END we1[3]
  PIN q1[0]
  USE SIGNAL ;
  DIRECTION OUTPUT ;
  PORT
      LAYER Metal3 ;
      RECT 40.730 0.000 41.010 14.190 ;
  END
  END q1[0]
  PIN q1[1]
  USE SIGNAL ;
  DIRECTION OUTPUT ;
  PORT
      LAYER Metal3 ;
      RECT 63.290 0.000 63.570 14.190 ;
  END
  END q1[1]
  PIN q1[2]
  USE SIGNAL ;
  DIRECTION OUTPUT ;
  PORT
      LAYER Metal3 ;
      RECT 85.850 0.000 86.130 14.190 ;
  END
  END q1[2]
  PIN q1[3]
  USE SIGNAL ;
  DIRECTION OUTPUT ;
  PORT
      LAYER Metal3 ;
      RECT 108.410 0.000 108.690 14.190 ;
  END
  END q1[3]
  PIN q1[4]
  USE SIGNAL ;
  DIRECTION OUTPUT ;
  PORT
      LAYER Metal3 ;
      RECT 130.970 0.000 131.250 14.190 ;
  END
  END q1[4]
  PIN q1[5]
  USE SIGNAL ;
  DIRECTION OUTPUT ;
  PORT
      LAYER Metal3 ;
      RECT 153.530 0.000 153.810 14.190 ;
  END
  END q1[5]
  PIN q1[6]
  USE SIGNAL ;
  DIRECTION OUTPUT ;
  PORT
      LAYER Metal3 ;
      RECT 176.090 0.000 176.370 14.190 ;
  END
  END q1[6]
  PIN q1[7]
  USE SIGNAL ;
  DIRECTION OUTPUT ;
  PORT
      LAYER Metal3 ;
      RECT 198.650 0.000 198.930 14.190 ;
  END
  END q1[7]
  PIN q1[8]
  USE SIGNAL ;
  DIRECTION OUTPUT ;
  PORT
      LAYER Metal3 ;
      RECT 221.210 0.000 221.490 14.190 ;
  END
  END q1[8]
  PIN q1[9]
  USE SIGNAL ;
  DIRECTION OUTPUT ;
  PORT
      LAYER Metal3 ;
      RECT 243.770 0.000 244.050 14.190 ;
  END
  END q1[9]
  PIN q1[10]
  USE SIGNAL ;
  DIRECTION OUTPUT ;
  PORT
      LAYER Metal3 ;
      RECT 266.330 0.000 266.610 14.190 ;
  END
  END q1[10]
  PIN q1[11]
  USE SIGNAL ;
  DIRECTION OUTPUT ;
  PORT
      LAYER Metal3 ;
      RECT 288.890 0.000 289.170 14.190 ;
  END
  END q1[11]
  PIN q1[12]
  USE SIGNAL ;
  DIRECTION OUTPUT ;
  PORT
      LAYER Metal3 ;
      RECT 311.450 0.000 311.730 14.190 ;
  END
  END q1[12]
  PIN q1[13]
  USE SIGNAL ;
  DIRECTION OUTPUT ;
  PORT
      LAYER Metal3 ;
      RECT 334.010 0.000 334.290 14.190 ;
  END
  END q1[13]
  PIN q1[14]
  USE SIGNAL ;
  DIRECTION OUTPUT ;
  PORT
      LAYER Metal3 ;
      RECT 356.570 0.000 356.850 14.190 ;
  END
  END q1[14]
  PIN q1[15]
  USE SIGNAL ;
  DIRECTION OUTPUT ;
  PORT
      LAYER Metal3 ;
      RECT 379.130 0.000 379.410 14.190 ;
  END
  END q1[15]
  PIN q1[16]
  USE SIGNAL ;
  DIRECTION OUTPUT ;
  PORT
      LAYER Metal3 ;
      RECT 401.690 0.000 401.970 14.190 ;
  END
  END q1[16]
  PIN q1[17]
  USE SIGNAL ;
  DIRECTION OUTPUT ;
  PORT
      LAYER Metal3 ;
      RECT 424.250 0.000 424.530 14.190 ;
  END
  END q1[17]
  PIN q1[18]
  USE SIGNAL ;
  DIRECTION OUTPUT ;
  PORT
      LAYER Metal3 ;
      RECT 446.810 0.000 447.090 14.190 ;
  END
  END q1[18]
  PIN q1[19]
  USE SIGNAL ;
  DIRECTION OUTPUT ;
  PORT
      LAYER Metal3 ;
      RECT 469.370 0.000 469.650 14.190 ;
  END
  END q1[19]
  PIN q1[20]
  USE SIGNAL ;
  DIRECTION OUTPUT ;
  PORT
      LAYER Metal3 ;
      RECT 491.930 0.000 492.210 14.190 ;
  END
  END q1[20]
  PIN q1[21]
  USE SIGNAL ;
  DIRECTION OUTPUT ;
  PORT
      LAYER Metal3 ;
      RECT 514.490 0.000 514.770 14.190 ;
  END
  END q1[21]
  PIN q1[22]
  USE SIGNAL ;
  DIRECTION OUTPUT ;
  PORT
      LAYER Metal3 ;
      RECT 537.050 0.000 537.330 14.190 ;
  END
  END q1[22]
  PIN q1[23]
  USE SIGNAL ;
  DIRECTION OUTPUT ;
  PORT
      LAYER Metal3 ;
      RECT 559.610 0.000 559.890 14.190 ;
  END
  END q1[23]
  PIN q1[24]
  USE SIGNAL ;
  DIRECTION OUTPUT ;
  PORT
      LAYER Metal3 ;
      RECT 582.170 0.000 582.450 14.190 ;
  END
  END q1[24]
  PIN q1[25]
  USE SIGNAL ;
  DIRECTION OUTPUT ;
  PORT
      LAYER Metal3 ;
      RECT 604.730 0.000 605.010 14.190 ;
  END
  END q1[25]
  PIN q1[26]
  USE SIGNAL ;
  DIRECTION OUTPUT ;
  PORT
      LAYER Metal3 ;
      RECT 627.290 0.000 627.570 14.190 ;
  END
  END q1[26]
  PIN q1[27]
  USE SIGNAL ;
  DIRECTION OUTPUT ;
  PORT
      LAYER Metal3 ;
      RECT 649.850 0.000 650.130 14.190 ;
  END
  END q1[27]
  PIN q1[28]
  USE SIGNAL ;
  DIRECTION OUTPUT ;
  PORT
      LAYER Metal3 ;
      RECT 672.410 0.000 672.690 14.190 ;
  END
  END q1[28]
  PIN q1[29]
  USE SIGNAL ;
  DIRECTION OUTPUT ;
  PORT
      LAYER Metal3 ;
      RECT 694.970 0.000 695.250 14.190 ;
  END
  END q1[29]
  PIN q1[30]
  USE SIGNAL ;
  DIRECTION OUTPUT ;
  PORT
      LAYER Metal3 ;
      RECT 717.530 0.000 717.810 14.190 ;
  END
  END q1[30]
  PIN q1[31]
  USE SIGNAL ;
  DIRECTION OUTPUT ;
  PORT
      LAYER Metal3 ;
      RECT 740.090 0.000 740.370 14.190 ;
  END
  END q1[31]
  PIN a2[0]
  USE SIGNAL ;
  DIRECTION INPUT ;
  ANTENNAGATEAREA 0.492800 ;
  PORT
      LAYER Metal3 ;
      RECT 792.620 259.510 795.600 259.790 ;
  END
  END a2[0]
  PIN a2[1]
  USE SIGNAL ;
  DIRECTION INPUT ;
  ANTENNAGATEAREA 0.492800 ;
  PORT
      LAYER Metal3 ;
      RECT 792.620 254.370 795.600 254.650 ;
  END
  END a2[1]
  PIN a2[2]
  USE SIGNAL ;
  DIRECTION INPUT ;
  ANTENNAGATEAREA 0.492800 ;
  PORT
      LAYER Metal3 ;
      RECT 793.090 242.970 795.600 243.250 ;
  END
  END a2[2]
  PIN a2[3]
  USE SIGNAL ;
  DIRECTION INPUT ;
  ANTENNAGATEAREA 0.492800 ;
  PORT
      LAYER Metal3 ;
      RECT 793.090 230.050 795.600 230.330 ;
  END
  END a2[3]
  PIN a2[4]
  USE SIGNAL ;
  DIRECTION INPUT ;
  ANTENNAGATEAREA 0.492800 ;
  PORT
      LAYER Metal3 ;
      RECT 793.090 217.130 795.600 217.410 ;
  END
  END a2[4]
  PIN a2[5]
  USE SIGNAL ;
  DIRECTION INPUT ;
  ANTENNAGATEAREA 0.492800 ;
  PORT
      LAYER Metal3 ;
      RECT 793.090 204.210 795.600 204.490 ;
  END
  END a2[5]
  PIN a2[6]
  USE SIGNAL ;
  DIRECTION INPUT ;
  ANTENNAGATEAREA 0.492800 ;
  PORT
      LAYER Metal3 ;
      RECT 793.090 191.290 795.600 191.570 ;
  END
  END a2[6]
  PIN a2[7]
  USE SIGNAL ;
  DIRECTION INPUT ;
  ANTENNAGATEAREA 0.492800 ;
  PORT
      LAYER Metal3 ;
      RECT 793.090 178.370 795.600 178.650 ;
  END
  END a2[7]
  PIN a2[8]
  USE SIGNAL ;
  DIRECTION INPUT ;
  ANTENNAGATEAREA 0.492800 ;
  PORT
      LAYER Metal3 ;
      RECT 793.090 165.450 795.600 165.730 ;
  END
  END a2[8]
  PIN d2[0]
  USE SIGNAL ;
  DIRECTION INPUT ;
  ANTENNAGATEAREA 0.492800 ;
  PORT
      LAYER Metal3 ;
      RECT 56.690 265.180 56.970 274.320 ;
  END
  END d2[0]
  PIN d2[1]
  USE SIGNAL ;
  DIRECTION INPUT ;
  ANTENNAGATEAREA 0.492800 ;
  PORT
      LAYER Metal3 ;
      RECT 79.250 265.180 79.530 274.320 ;
  END
  END d2[1]
  PIN d2[2]
  USE SIGNAL ;
  DIRECTION INPUT ;
  ANTENNAGATEAREA 0.492800 ;
  PORT
      LAYER Metal3 ;
      RECT 101.810 265.180 102.090 274.320 ;
  END
  END d2[2]
  PIN d2[3]
  USE SIGNAL ;
  DIRECTION INPUT ;
  ANTENNAGATEAREA 0.492800 ;
  PORT
      LAYER Metal3 ;
      RECT 124.370 265.180 124.650 274.320 ;
  END
  END d2[3]
  PIN d2[4]
  USE SIGNAL ;
  DIRECTION INPUT ;
  ANTENNAGATEAREA 0.492800 ;
  PORT
      LAYER Metal3 ;
      RECT 146.930 265.180 147.210 274.320 ;
  END
  END d2[4]
  PIN d2[5]
  USE SIGNAL ;
  DIRECTION INPUT ;
  ANTENNAGATEAREA 0.492800 ;
  PORT
      LAYER Metal3 ;
      RECT 169.490 265.180 169.770 274.320 ;
  END
  END d2[5]
  PIN d2[6]
  USE SIGNAL ;
  DIRECTION INPUT ;
  ANTENNAGATEAREA 0.492800 ;
  PORT
      LAYER Metal3 ;
      RECT 192.050 265.180 192.330 274.320 ;
  END
  END d2[6]
  PIN d2[7]
  USE SIGNAL ;
  DIRECTION INPUT ;
  ANTENNAGATEAREA 0.492800 ;
  PORT
      LAYER Metal3 ;
      RECT 214.610 265.180 214.890 274.320 ;
  END
  END d2[7]
  PIN d2[8]
  USE SIGNAL ;
  DIRECTION INPUT ;
  ANTENNAGATEAREA 0.492800 ;
  PORT
      LAYER Metal3 ;
      RECT 237.170 265.180 237.450 274.320 ;
  END
  END d2[8]
  PIN d2[9]
  USE SIGNAL ;
  DIRECTION INPUT ;
  ANTENNAGATEAREA 0.492800 ;
  PORT
      LAYER Metal3 ;
      RECT 259.730 265.180 260.010 274.320 ;
  END
  END d2[9]
  PIN d2[10]
  USE SIGNAL ;
  DIRECTION INPUT ;
  ANTENNAGATEAREA 0.492800 ;
  PORT
      LAYER Metal3 ;
      RECT 282.290 265.180 282.570 274.320 ;
  END
  END d2[10]
  PIN d2[11]
  USE SIGNAL ;
  DIRECTION INPUT ;
  ANTENNAGATEAREA 0.492800 ;
  PORT
      LAYER Metal3 ;
      RECT 304.850 265.180 305.130 274.320 ;
  END
  END d2[11]
  PIN d2[12]
  USE SIGNAL ;
  DIRECTION INPUT ;
  ANTENNAGATEAREA 0.492800 ;
  PORT
      LAYER Metal3 ;
      RECT 327.410 265.180 327.690 274.320 ;
  END
  END d2[12]
  PIN d2[13]
  USE SIGNAL ;
  DIRECTION INPUT ;
  ANTENNAGATEAREA 0.492800 ;
  PORT
      LAYER Metal3 ;
      RECT 349.970 265.180 350.250 274.320 ;
  END
  END d2[13]
  PIN d2[14]
  USE SIGNAL ;
  DIRECTION INPUT ;
  ANTENNAGATEAREA 0.492800 ;
  PORT
      LAYER Metal3 ;
      RECT 372.530 265.180 372.810 274.320 ;
  END
  END d2[14]
  PIN d2[15]
  USE SIGNAL ;
  DIRECTION INPUT ;
  ANTENNAGATEAREA 0.492800 ;
  PORT
      LAYER Metal3 ;
      RECT 395.090 265.180 395.370 274.320 ;
  END
  END d2[15]
  PIN d2[16]
  USE SIGNAL ;
  DIRECTION INPUT ;
  ANTENNAGATEAREA 0.492800 ;
  PORT
      LAYER Metal3 ;
      RECT 417.650 265.180 417.930 274.320 ;
  END
  END d2[16]
  PIN d2[17]
  USE SIGNAL ;
  DIRECTION INPUT ;
  ANTENNAGATEAREA 0.492800 ;
  PORT
      LAYER Metal3 ;
      RECT 440.210 265.180 440.490 274.320 ;
  END
  END d2[17]
  PIN d2[18]
  USE SIGNAL ;
  DIRECTION INPUT ;
  ANTENNAGATEAREA 0.492800 ;
  PORT
      LAYER Metal3 ;
      RECT 462.770 265.180 463.050 274.320 ;
  END
  END d2[18]
  PIN d2[19]
  USE SIGNAL ;
  DIRECTION INPUT ;
  ANTENNAGATEAREA 0.492800 ;
  PORT
      LAYER Metal3 ;
      RECT 485.330 265.180 485.610 274.320 ;
  END
  END d2[19]
  PIN d2[20]
  USE SIGNAL ;
  DIRECTION INPUT ;
  ANTENNAGATEAREA 0.492800 ;
  PORT
      LAYER Metal3 ;
      RECT 507.890 265.180 508.170 274.320 ;
  END
  END d2[20]
  PIN d2[21]
  USE SIGNAL ;
  DIRECTION INPUT ;
  ANTENNAGATEAREA 0.492800 ;
  PORT
      LAYER Metal3 ;
      RECT 530.450 265.180 530.730 274.320 ;
  END
  END d2[21]
  PIN d2[22]
  USE SIGNAL ;
  DIRECTION INPUT ;
  ANTENNAGATEAREA 0.492800 ;
  PORT
      LAYER Metal3 ;
      RECT 553.010 265.180 553.290 274.320 ;
  END
  END d2[22]
  PIN d2[23]
  USE SIGNAL ;
  DIRECTION INPUT ;
  ANTENNAGATEAREA 0.492800 ;
  PORT
      LAYER Metal3 ;
      RECT 575.570 265.180 575.850 274.320 ;
  END
  END d2[23]
  PIN d2[24]
  USE SIGNAL ;
  DIRECTION INPUT ;
  ANTENNAGATEAREA 0.492800 ;
  PORT
      LAYER Metal3 ;
      RECT 598.130 265.180 598.410 274.320 ;
  END
  END d2[24]
  PIN d2[25]
  USE SIGNAL ;
  DIRECTION INPUT ;
  ANTENNAGATEAREA 0.492800 ;
  PORT
      LAYER Metal3 ;
      RECT 620.690 265.180 620.970 274.320 ;
  END
  END d2[25]
  PIN d2[26]
  USE SIGNAL ;
  DIRECTION INPUT ;
  ANTENNAGATEAREA 0.492800 ;
  PORT
      LAYER Metal3 ;
      RECT 643.250 265.180 643.530 274.320 ;
  END
  END d2[26]
  PIN d2[27]
  USE SIGNAL ;
  DIRECTION INPUT ;
  ANTENNAGATEAREA 0.492800 ;
  PORT
      LAYER Metal3 ;
      RECT 665.810 265.180 666.090 274.320 ;
  END
  END d2[27]
  PIN d2[28]
  USE SIGNAL ;
  DIRECTION INPUT ;
  ANTENNAGATEAREA 0.492800 ;
  PORT
      LAYER Metal3 ;
      RECT 688.370 265.180 688.650 274.320 ;
  END
  END d2[28]
  PIN d2[29]
  USE SIGNAL ;
  DIRECTION INPUT ;
  ANTENNAGATEAREA 0.492800 ;
  PORT
      LAYER Metal3 ;
      RECT 710.930 265.180 711.210 274.320 ;
  END
  END d2[29]
  PIN d2[30]
  USE SIGNAL ;
  DIRECTION INPUT ;
  ANTENNAGATEAREA 0.492800 ;
  PORT
      LAYER Metal3 ;
      RECT 733.490 265.180 733.770 274.320 ;
  END
  END d2[30]
  PIN d2[31]
  USE SIGNAL ;
  DIRECTION INPUT ;
  ANTENNAGATEAREA 0.492800 ;
  PORT
      LAYER Metal3 ;
      RECT 756.050 265.180 756.330 274.320 ;
  END
  END d2[31]
  PIN we2[0]
  USE SIGNAL ;
  DIRECTION INPUT ;
  ANTENNAGATEAREA 0.492800 ;
  PORT
      LAYER Metal3 ;
      RECT 47.810 273.320 48.090 274.320 ;
  END
  END we2[0]
  PIN we2[1]
  USE SIGNAL ;
  DIRECTION INPUT ;
  ANTENNAGATEAREA 0.492800 ;
  PORT
      LAYER Metal3 ;
      RECT 228.290 273.320 228.570 274.320 ;
  END
  END we2[1]
  PIN we2[2]
  USE SIGNAL ;
  DIRECTION INPUT ;
  ANTENNAGATEAREA 0.492800 ;
  PORT
      LAYER Metal3 ;
      RECT 408.770 273.320 409.050 274.320 ;
  END
  END we2[2]
  PIN we2[3]
  USE SIGNAL ;
  DIRECTION INPUT ;
  ANTENNAGATEAREA 0.492800 ;
  PORT
      LAYER Metal3 ;
      RECT 589.250 273.320 589.530 274.320 ;
  END
  END we2[3]
  PIN q2[0]
  USE SIGNAL ;
  DIRECTION OUTPUT ;
  PORT
      LAYER Metal3 ;
      RECT 55.230 260.130 55.510 274.320 ;
  END
  END q2[0]
  PIN q2[1]
  USE SIGNAL ;
  DIRECTION OUTPUT ;
  PORT
      LAYER Metal3 ;
      RECT 77.790 260.130 78.070 274.320 ;
  END
  END q2[1]
  PIN q2[2]
  USE SIGNAL ;
  DIRECTION OUTPUT ;
  PORT
      LAYER Metal3 ;
      RECT 100.350 260.130 100.630 274.320 ;
  END
  END q2[2]
  PIN q2[3]
  USE SIGNAL ;
  DIRECTION OUTPUT ;
  PORT
      LAYER Metal3 ;
      RECT 122.910 260.130 123.190 274.320 ;
  END
  END q2[3]
  PIN q2[4]
  USE SIGNAL ;
  DIRECTION OUTPUT ;
  PORT
      LAYER Metal3 ;
      RECT 145.470 260.130 145.750 274.320 ;
  END
  END q2[4]
  PIN q2[5]
  USE SIGNAL ;
  DIRECTION OUTPUT ;
  PORT
      LAYER Metal3 ;
      RECT 168.030 260.130 168.310 274.320 ;
  END
  END q2[5]
  PIN q2[6]
  USE SIGNAL ;
  DIRECTION OUTPUT ;
  PORT
      LAYER Metal3 ;
      RECT 190.590 260.130 190.870 274.320 ;
  END
  END q2[6]
  PIN q2[7]
  USE SIGNAL ;
  DIRECTION OUTPUT ;
  PORT
      LAYER Metal3 ;
      RECT 213.150 260.130 213.430 274.320 ;
  END
  END q2[7]
  PIN q2[8]
  USE SIGNAL ;
  DIRECTION OUTPUT ;
  PORT
      LAYER Metal3 ;
      RECT 235.710 260.130 235.990 274.320 ;
  END
  END q2[8]
  PIN q2[9]
  USE SIGNAL ;
  DIRECTION OUTPUT ;
  PORT
      LAYER Metal3 ;
      RECT 258.270 260.130 258.550 274.320 ;
  END
  END q2[9]
  PIN q2[10]
  USE SIGNAL ;
  DIRECTION OUTPUT ;
  PORT
      LAYER Metal3 ;
      RECT 280.830 260.130 281.110 274.320 ;
  END
  END q2[10]
  PIN q2[11]
  USE SIGNAL ;
  DIRECTION OUTPUT ;
  PORT
      LAYER Metal3 ;
      RECT 303.390 260.130 303.670 274.320 ;
  END
  END q2[11]
  PIN q2[12]
  USE SIGNAL ;
  DIRECTION OUTPUT ;
  PORT
      LAYER Metal3 ;
      RECT 325.950 260.130 326.230 274.320 ;
  END
  END q2[12]
  PIN q2[13]
  USE SIGNAL ;
  DIRECTION OUTPUT ;
  PORT
      LAYER Metal3 ;
      RECT 348.510 260.130 348.790 274.320 ;
  END
  END q2[13]
  PIN q2[14]
  USE SIGNAL ;
  DIRECTION OUTPUT ;
  PORT
      LAYER Metal3 ;
      RECT 371.070 260.130 371.350 274.320 ;
  END
  END q2[14]
  PIN q2[15]
  USE SIGNAL ;
  DIRECTION OUTPUT ;
  PORT
      LAYER Metal3 ;
      RECT 393.630 260.130 393.910 274.320 ;
  END
  END q2[15]
  PIN q2[16]
  USE SIGNAL ;
  DIRECTION OUTPUT ;
  PORT
      LAYER Metal3 ;
      RECT 416.190 260.130 416.470 274.320 ;
  END
  END q2[16]
  PIN q2[17]
  USE SIGNAL ;
  DIRECTION OUTPUT ;
  PORT
      LAYER Metal3 ;
      RECT 438.750 260.130 439.030 274.320 ;
  END
  END q2[17]
  PIN q2[18]
  USE SIGNAL ;
  DIRECTION OUTPUT ;
  PORT
      LAYER Metal3 ;
      RECT 461.310 260.130 461.590 274.320 ;
  END
  END q2[18]
  PIN q2[19]
  USE SIGNAL ;
  DIRECTION OUTPUT ;
  PORT
      LAYER Metal3 ;
      RECT 483.870 260.130 484.150 274.320 ;
  END
  END q2[19]
  PIN q2[20]
  USE SIGNAL ;
  DIRECTION OUTPUT ;
  PORT
      LAYER Metal3 ;
      RECT 506.430 260.130 506.710 274.320 ;
  END
  END q2[20]
  PIN q2[21]
  USE SIGNAL ;
  DIRECTION OUTPUT ;
  PORT
      LAYER Metal3 ;
      RECT 528.990 260.130 529.270 274.320 ;
  END
  END q2[21]
  PIN q2[22]
  USE SIGNAL ;
  DIRECTION OUTPUT ;
  PORT
      LAYER Metal3 ;
      RECT 551.550 260.130 551.830 274.320 ;
  END
  END q2[22]
  PIN q2[23]
  USE SIGNAL ;
  DIRECTION OUTPUT ;
  PORT
      LAYER Metal3 ;
      RECT 574.110 260.130 574.390 274.320 ;
  END
  END q2[23]
  PIN q2[24]
  USE SIGNAL ;
  DIRECTION OUTPUT ;
  PORT
      LAYER Metal3 ;
      RECT 596.670 260.130 596.950 274.320 ;
  END
  END q2[24]
  PIN q2[25]
  USE SIGNAL ;
  DIRECTION OUTPUT ;
  PORT
      LAYER Metal3 ;
      RECT 619.230 260.130 619.510 274.320 ;
  END
  END q2[25]
  PIN q2[26]
  USE SIGNAL ;
  DIRECTION OUTPUT ;
  PORT
      LAYER Metal3 ;
      RECT 641.790 260.130 642.070 274.320 ;
  END
  END q2[26]
  PIN q2[27]
  USE SIGNAL ;
  DIRECTION OUTPUT ;
  PORT
      LAYER Metal3 ;
      RECT 664.350 260.130 664.630 274.320 ;
  END
  END q2[27]
  PIN q2[28]
  USE SIGNAL ;
  DIRECTION OUTPUT ;
  PORT
      LAYER Metal3 ;
      RECT 686.910 260.130 687.190 274.320 ;
  END
  END q2[28]
  PIN q2[29]
  USE SIGNAL ;
  DIRECTION OUTPUT ;
  PORT
      LAYER Metal3 ;
      RECT 709.470 260.130 709.750 274.320 ;
  END
  END q2[29]
  PIN q2[30]
  USE SIGNAL ;
  DIRECTION OUTPUT ;
  PORT
      LAYER Metal3 ;
      RECT 732.030 260.130 732.310 274.320 ;
  END
  END q2[30]
  PIN q2[31]
  USE SIGNAL ;
  DIRECTION OUTPUT ;
  PORT
      LAYER Metal3 ;
      RECT 754.590 260.130 754.870 274.320 ;
  END
  END q2[31]
  PIN vss
    USE GROUND ;
    DIRECTION INOUT ;
    PORT
      LAYER Metal3 ;
        RECT 36.840 217.500 758.760 217.900 ;
    END
    PORT
      LAYER Metal3 ;
        RECT 36.840 190.540 758.760 190.940 ;
    END
    PORT
      LAYER Metal3 ;
        RECT 36.840 254.540 758.760 255.540 ;
    END
    PORT
      LAYER Metal3 ;
        RECT 36.840 244.460 758.760 244.860 ;
    END
    PORT
      LAYER Metal3 ;
        RECT 36.840 251.045 758.760 251.325 ;
    END
    PORT
      LAYER Metal3 ;
        RECT 36.840 109.660 758.760 110.060 ;
    END
    PORT
      LAYER Metal3 ;
        RECT 36.840 22.995 758.760 23.275 ;
    END
    PORT
      LAYER Metal3 ;
        RECT 36.840 82.700 758.760 83.100 ;
    END
    PORT
      LAYER Metal3 ;
        RECT 36.840 18.780 758.760 19.780 ;
    END
    PORT
      LAYER Metal3 ;
        RECT 36.840 163.580 758.760 163.980 ;
    END
    PORT
      LAYER Metal3 ;
        RECT 36.840 28.780 758.760 29.180 ;
    END
    PORT
      LAYER Metal3 ;
        RECT 36.840 55.740 758.760 56.140 ;
    END
    PORT
      LAYER Metal3 ;
        RECT 36.840 136.620 758.760 137.020 ;
    END
  END vss
  PIN vdd
    USE POWER ;
    DIRECTION INOUT ;
    PORT
      LAYER Metal3 ;
        RECT 36.840 29.460 758.760 29.860 ;
    END
    PORT
      LAYER Metal3 ;
        RECT 36.840 245.140 758.760 245.540 ;
    END
    PORT
      LAYER Metal3 ;
        RECT 36.840 20.060 758.760 21.060 ;
    END
    PORT
      LAYER Metal3 ;
        RECT 36.840 110.340 758.760 110.740 ;
    END
    PORT
      LAYER Metal3 ;
        RECT 36.840 191.220 758.760 191.620 ;
    END
    PORT
      LAYER Metal3 ;
        RECT 36.840 218.180 758.760 218.580 ;
    END
    PORT
      LAYER Metal3 ;
        RECT 36.840 246.750 758.950 247.030 ;
    END
    PORT
      LAYER Metal3 ;
        RECT 36.840 56.420 758.760 56.820 ;
    END
    PORT
      LAYER Metal3 ;
        RECT 36.840 164.260 758.760 164.660 ;
    END
    PORT
      LAYER Metal3 ;
        RECT 36.650 27.290 758.760 27.570 ;
    END
    PORT
      LAYER Metal3 ;
        RECT 36.840 253.260 758.760 254.260 ;
    END
    PORT
      LAYER Metal3 ;
        RECT 36.840 137.300 758.760 137.700 ;
    END
    PORT
      LAYER Metal3 ;
        RECT 36.840 83.380 758.760 83.780 ;
    END
  END vdd
  OBS
    LAYER Metal1 ;
      RECT 0.000 0.000 795.600 274.320 ;
    LAYER Metal2 ;
      RECT 0.000 0.000 795.600 274.320 ;
    LAYER Metal3 ;
      RECT 0.000 0.000 795.600 274.320 ;
  END
END DP8TRBlock_512x32

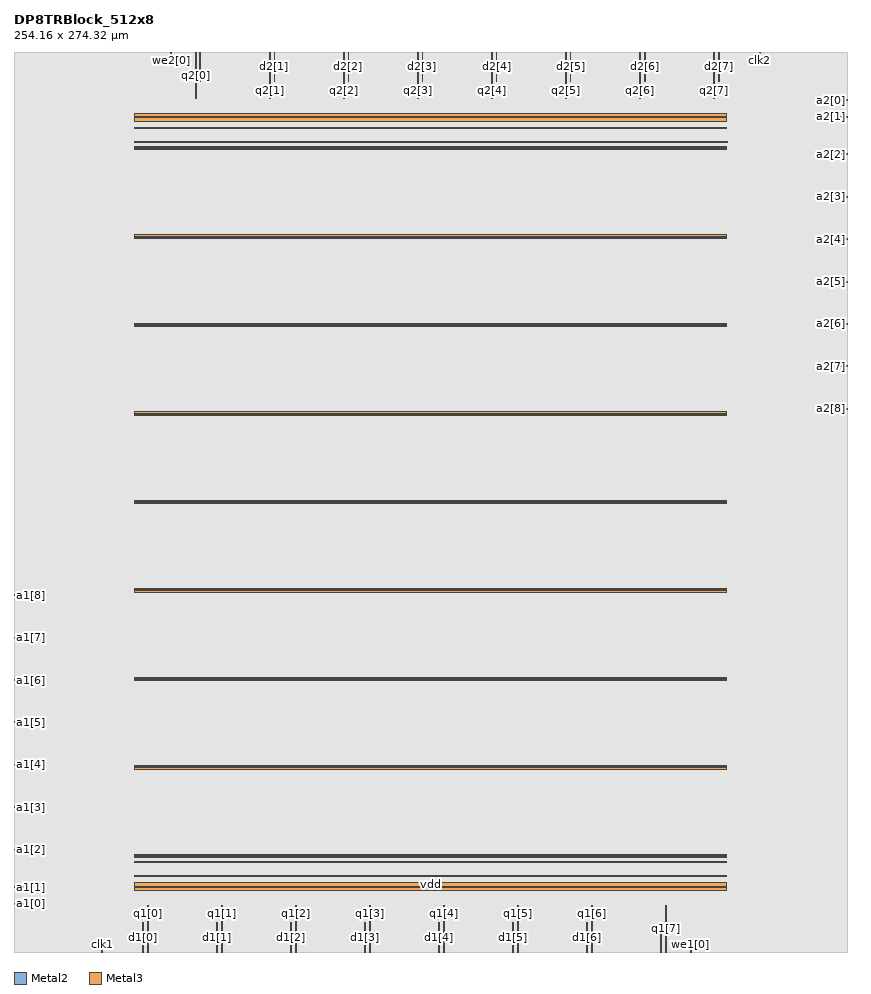
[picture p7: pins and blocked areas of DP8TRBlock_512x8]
MACRO DP8TRBlock_512x8
  CLASS BLOCK ;
  FOREIGN DP8TRBlock_512x8 ;
  ORIGIN 0.000 0.000 ;
  SIZE 254.160 BY 274.320 ;
  SYMMETRY X Y R90 ;
  PIN clk1
  USE CLOCK ;
  DIRECTION INPUT ;
  ANTENNAGATEAREA 0.492800 ;
  PORT
      LAYER Metal2 ;
      RECT 26.655 0.000 27.035 1.900 ;
  END
  END clk1
  PIN clk2
  USE CLOCK ;
  DIRECTION INPUT ;
  ANTENNAGATEAREA 0.492800 ;
  PORT
      LAYER Metal2 ;
      RECT 227.125 272.420 227.505 274.320 ;
  END
  END clk2
  PIN a1[0]
  USE SIGNAL ;
  DIRECTION INPUT ;
  ANTENNAGATEAREA 0.492800 ;
  PORT
      LAYER Metal3 ;
      RECT 0.000 14.530 2.980 14.810 ;
  END
  END a1[0]
  PIN a1[1]
  USE SIGNAL ;
  DIRECTION INPUT ;
  ANTENNAGATEAREA 0.492800 ;
  PORT
      LAYER Metal3 ;
      RECT 0.000 19.670 2.980 19.950 ;
  END
  END a1[1]
  PIN a1[2]
  USE SIGNAL ;
  DIRECTION INPUT ;
  ANTENNAGATEAREA 0.492800 ;
  PORT
      LAYER Metal3 ;
      RECT 0.000 31.070 2.510 31.350 ;
  END
  END a1[2]
  PIN a1[3]
  USE SIGNAL ;
  DIRECTION INPUT ;
  ANTENNAGATEAREA 0.492800 ;
  PORT
      LAYER Metal3 ;
      RECT 0.000 43.990 2.510 44.270 ;
  END
  END a1[3]
  PIN a1[4]
  USE SIGNAL ;
  DIRECTION INPUT ;
  ANTENNAGATEAREA 0.492800 ;
  PORT
      LAYER Metal3 ;
      RECT 0.000 56.910 2.510 57.190 ;
  END
  END a1[4]
  PIN a1[5]
  USE SIGNAL ;
  DIRECTION INPUT ;
  ANTENNAGATEAREA 0.492800 ;
  PORT
      LAYER Metal3 ;
      RECT 0.000 69.830 2.510 70.110 ;
  END
  END a1[5]
  PIN a1[6]
  USE SIGNAL ;
  DIRECTION INPUT ;
  ANTENNAGATEAREA 0.492800 ;
  PORT
      LAYER Metal3 ;
      RECT 0.000 82.750 2.510 83.030 ;
  END
  END a1[6]
  PIN a1[7]
  USE SIGNAL ;
  DIRECTION INPUT ;
  ANTENNAGATEAREA 0.492800 ;
  PORT
      LAYER Metal3 ;
      RECT 0.000 95.670 2.510 95.950 ;
  END
  END a1[7]
  PIN a1[8]
  USE SIGNAL ;
  DIRECTION INPUT ;
  ANTENNAGATEAREA 0.492800 ;
  PORT
      LAYER Metal3 ;
      RECT 0.000 108.590 2.510 108.870 ;
  END
  END a1[8]
  PIN d1[0]
  USE SIGNAL ;
  DIRECTION INPUT ;
  ANTENNAGATEAREA 0.492800 ;
  PORT
      LAYER Metal3 ;
      RECT 39.270 0.000 39.550 9.140 ;
  END
  END d1[0]
  PIN d1[1]
  USE SIGNAL ;
  DIRECTION INPUT ;
  ANTENNAGATEAREA 0.492800 ;
  PORT
      LAYER Metal3 ;
      RECT 61.830 0.000 62.110 9.140 ;
  END
  END d1[1]
  PIN d1[2]
  USE SIGNAL ;
  DIRECTION INPUT ;
  ANTENNAGATEAREA 0.492800 ;
  PORT
      LAYER Metal3 ;
      RECT 84.390 0.000 84.670 9.140 ;
  END
  END d1[2]
  PIN d1[3]
  USE SIGNAL ;
  DIRECTION INPUT ;
  ANTENNAGATEAREA 0.492800 ;
  PORT
      LAYER Metal3 ;
      RECT 106.950 0.000 107.230 9.140 ;
  END
  END d1[3]
  PIN d1[4]
  USE SIGNAL ;
  DIRECTION INPUT ;
  ANTENNAGATEAREA 0.492800 ;
  PORT
      LAYER Metal3 ;
      RECT 129.510 0.000 129.790 9.140 ;
  END
  END d1[4]
  PIN d1[5]
  USE SIGNAL ;
  DIRECTION INPUT ;
  ANTENNAGATEAREA 0.492800 ;
  PORT
      LAYER Metal3 ;
      RECT 152.070 0.000 152.350 9.140 ;
  END
  END d1[5]
  PIN d1[6]
  USE SIGNAL ;
  DIRECTION INPUT ;
  ANTENNAGATEAREA 0.492800 ;
  PORT
      LAYER Metal3 ;
      RECT 174.630 0.000 174.910 9.140 ;
  END
  END d1[6]
  PIN d1[7]
  USE SIGNAL ;
  DIRECTION INPUT ;
  ANTENNAGATEAREA 0.492800 ;
  PORT
      LAYER Metal3 ;
      RECT 197.190 0.000 197.470 9.140 ;
  END
  END d1[7]
  PIN we1[0]
  USE SIGNAL ;
  DIRECTION INPUT ;
  ANTENNAGATEAREA 0.492800 ;
  PORT
      LAYER Metal3 ;
      RECT 206.070 0.000 206.350 1.000 ;
  END
  END we1[0]
  PIN q1[0]
  USE SIGNAL ;
  DIRECTION OUTPUT ;
  PORT
      LAYER Metal3 ;
      RECT 40.730 0.000 41.010 14.190 ;
  END
  END q1[0]
  PIN q1[1]
  USE SIGNAL ;
  DIRECTION OUTPUT ;
  PORT
      LAYER Metal3 ;
      RECT 63.290 0.000 63.570 14.190 ;
  END
  END q1[1]
  PIN q1[2]
  USE SIGNAL ;
  DIRECTION OUTPUT ;
  PORT
      LAYER Metal3 ;
      RECT 85.850 0.000 86.130 14.190 ;
  END
  END q1[2]
  PIN q1[3]
  USE SIGNAL ;
  DIRECTION OUTPUT ;
  PORT
      LAYER Metal3 ;
      RECT 108.410 0.000 108.690 14.190 ;
  END
  END q1[3]
  PIN q1[4]
  USE SIGNAL ;
  DIRECTION OUTPUT ;
  PORT
      LAYER Metal3 ;
      RECT 130.970 0.000 131.250 14.190 ;
  END
  END q1[4]
  PIN q1[5]
  USE SIGNAL ;
  DIRECTION OUTPUT ;
  PORT
      LAYER Metal3 ;
      RECT 153.530 0.000 153.810 14.190 ;
  END
  END q1[5]
  PIN q1[6]
  USE SIGNAL ;
  DIRECTION OUTPUT ;
  PORT
      LAYER Metal3 ;
      RECT 176.090 0.000 176.370 14.190 ;
  END
  END q1[6]
  PIN q1[7]
  USE SIGNAL ;
  DIRECTION OUTPUT ;
  PORT
      LAYER Metal3 ;
      RECT 198.650 0.000 198.930 14.190 ;
  END
  END q1[7]
  PIN a2[0]
  USE SIGNAL ;
  DIRECTION INPUT ;
  ANTENNAGATEAREA 0.492800 ;
  PORT
      LAYER Metal3 ;
      RECT 251.180 259.510 254.160 259.790 ;
  END
  END a2[0]
  PIN a2[1]
  USE SIGNAL ;
  DIRECTION INPUT ;
  ANTENNAGATEAREA 0.492800 ;
  PORT
      LAYER Metal3 ;
      RECT 251.180 254.370 254.160 254.650 ;
  END
  END a2[1]
  PIN a2[2]
  USE SIGNAL ;
  DIRECTION INPUT ;
  ANTENNAGATEAREA 0.492800 ;
  PORT
      LAYER Metal3 ;
      RECT 251.650 242.970 254.160 243.250 ;
  END
  END a2[2]
  PIN a2[3]
  USE SIGNAL ;
  DIRECTION INPUT ;
  ANTENNAGATEAREA 0.492800 ;
  PORT
      LAYER Metal3 ;
      RECT 251.650 230.050 254.160 230.330 ;
  END
  END a2[3]
  PIN a2[4]
  USE SIGNAL ;
  DIRECTION INPUT ;
  ANTENNAGATEAREA 0.492800 ;
  PORT
      LAYER Metal3 ;
      RECT 251.650 217.130 254.160 217.410 ;
  END
  END a2[4]
  PIN a2[5]
  USE SIGNAL ;
  DIRECTION INPUT ;
  ANTENNAGATEAREA 0.492800 ;
  PORT
      LAYER Metal3 ;
      RECT 251.650 204.210 254.160 204.490 ;
  END
  END a2[5]
  PIN a2[6]
  USE SIGNAL ;
  DIRECTION INPUT ;
  ANTENNAGATEAREA 0.492800 ;
  PORT
      LAYER Metal3 ;
      RECT 251.650 191.290 254.160 191.570 ;
  END
  END a2[6]
  PIN a2[7]
  USE SIGNAL ;
  DIRECTION INPUT ;
  ANTENNAGATEAREA 0.492800 ;
  PORT
      LAYER Metal3 ;
      RECT 251.650 178.370 254.160 178.650 ;
  END
  END a2[7]
  PIN a2[8]
  USE SIGNAL ;
  DIRECTION INPUT ;
  ANTENNAGATEAREA 0.492800 ;
  PORT
      LAYER Metal3 ;
      RECT 251.650 165.450 254.160 165.730 ;
  END
  END a2[8]
  PIN d2[0]
  USE SIGNAL ;
  DIRECTION INPUT ;
  ANTENNAGATEAREA 0.492800 ;
  PORT
      LAYER Metal3 ;
      RECT 56.690 265.180 56.970 274.320 ;
  END
  END d2[0]
  PIN d2[1]
  USE SIGNAL ;
  DIRECTION INPUT ;
  ANTENNAGATEAREA 0.492800 ;
  PORT
      LAYER Metal3 ;
      RECT 79.250 265.180 79.530 274.320 ;
  END
  END d2[1]
  PIN d2[2]
  USE SIGNAL ;
  DIRECTION INPUT ;
  ANTENNAGATEAREA 0.492800 ;
  PORT
      LAYER Metal3 ;
      RECT 101.810 265.180 102.090 274.320 ;
  END
  END d2[2]
  PIN d2[3]
  USE SIGNAL ;
  DIRECTION INPUT ;
  ANTENNAGATEAREA 0.492800 ;
  PORT
      LAYER Metal3 ;
      RECT 124.370 265.180 124.650 274.320 ;
  END
  END d2[3]
  PIN d2[4]
  USE SIGNAL ;
  DIRECTION INPUT ;
  ANTENNAGATEAREA 0.492800 ;
  PORT
      LAYER Metal3 ;
      RECT 146.930 265.180 147.210 274.320 ;
  END
  END d2[4]
  PIN d2[5]
  USE SIGNAL ;
  DIRECTION INPUT ;
  ANTENNAGATEAREA 0.492800 ;
  PORT
      LAYER Metal3 ;
      RECT 169.490 265.180 169.770 274.320 ;
  END
  END d2[5]
  PIN d2[6]
  USE SIGNAL ;
  DIRECTION INPUT ;
  ANTENNAGATEAREA 0.492800 ;
  PORT
      LAYER Metal3 ;
      RECT 192.050 265.180 192.330 274.320 ;
  END
  END d2[6]
  PIN d2[7]
  USE SIGNAL ;
  DIRECTION INPUT ;
  ANTENNAGATEAREA 0.492800 ;
  PORT
      LAYER Metal3 ;
      RECT 214.610 265.180 214.890 274.320 ;
  END
  END d2[7]
  PIN we2[0]
  USE SIGNAL ;
  DIRECTION INPUT ;
  ANTENNAGATEAREA 0.492800 ;
  PORT
      LAYER Metal3 ;
      RECT 47.810 273.320 48.090 274.320 ;
  END
  END we2[0]
  PIN q2[0]
  USE SIGNAL ;
  DIRECTION OUTPUT ;
  PORT
      LAYER Metal3 ;
      RECT 55.230 260.130 55.510 274.320 ;
  END
  END q2[0]
  PIN q2[1]
  USE SIGNAL ;
  DIRECTION OUTPUT ;
  PORT
      LAYER Metal3 ;
      RECT 77.790 260.130 78.070 274.320 ;
  END
  END q2[1]
  PIN q2[2]
  USE SIGNAL ;
  DIRECTION OUTPUT ;
  PORT
      LAYER Metal3 ;
      RECT 100.350 260.130 100.630 274.320 ;
  END
  END q2[2]
  PIN q2[3]
  USE SIGNAL ;
  DIRECTION OUTPUT ;
  PORT
      LAYER Metal3 ;
      RECT 122.910 260.130 123.190 274.320 ;
  END
  END q2[3]
  PIN q2[4]
  USE SIGNAL ;
  DIRECTION OUTPUT ;
  PORT
      LAYER Metal3 ;
      RECT 145.470 260.130 145.750 274.320 ;
  END
  END q2[4]
  PIN q2[5]
  USE SIGNAL ;
  DIRECTION OUTPUT ;
  PORT
      LAYER Metal3 ;
      RECT 168.030 260.130 168.310 274.320 ;
  END
  END q2[5]
  PIN q2[6]
  USE SIGNAL ;
  DIRECTION OUTPUT ;
  PORT
      LAYER Metal3 ;
      RECT 190.590 260.130 190.870 274.320 ;
  END
  END q2[6]
  PIN q2[7]
  USE SIGNAL ;
  DIRECTION OUTPUT ;
  PORT
      LAYER Metal3 ;
      RECT 213.150 260.130 213.430 274.320 ;
  END
  END q2[7]
  PIN vss
    USE GROUND ;
    DIRECTION INOUT ;
    PORT
      LAYER Metal3 ;
        RECT 36.840 109.660 217.320 110.060 ;
    END
    PORT
      LAYER Metal3 ;
        RECT 36.840 244.460 217.320 244.860 ;
    END
    PORT
      LAYER Metal3 ;
        RECT 36.840 190.540 217.320 190.940 ;
    END
    PORT
      LAYER Metal3 ;
        RECT 36.840 18.780 217.320 19.780 ;
    END
    PORT
      LAYER Metal3 ;
        RECT 36.840 28.780 217.320 29.180 ;
    END
    PORT
      LAYER Metal3 ;
        RECT 36.840 136.620 217.320 137.020 ;
    END
    PORT
      LAYER Metal3 ;
        RECT 36.840 22.995 217.320 23.275 ;
    END
    PORT
      LAYER Metal3 ;
        RECT 36.840 82.700 217.320 83.100 ;
    END
    PORT
      LAYER Metal3 ;
        RECT 36.840 55.740 217.320 56.140 ;
    END
    PORT
      LAYER Metal3 ;
        RECT 36.840 251.045 217.320 251.325 ;
    END
    PORT
      LAYER Metal3 ;
        RECT 36.840 254.540 217.320 255.540 ;
    END
    PORT
      LAYER Metal3 ;
        RECT 36.840 163.580 217.320 163.980 ;
    END
    PORT
      LAYER Metal3 ;
        RECT 36.840 217.500 217.320 217.900 ;
    END
  END vss
  PIN vdd
    USE POWER ;
    DIRECTION INOUT ;
    PORT
      LAYER Metal3 ;
        RECT 36.840 56.420 217.320 56.820 ;
    END
    PORT
      LAYER Metal3 ;
        RECT 36.840 29.460 217.320 29.860 ;
    END
    PORT
      LAYER Metal3 ;
        RECT 36.840 164.260 217.320 164.660 ;
    END
    PORT
      LAYER Metal3 ;
        RECT 36.840 218.180 217.320 218.580 ;
    END
    PORT
      LAYER Metal3 ;
        RECT 36.840 20.060 217.320 21.060 ;
    END
    PORT
      LAYER Metal3 ;
        RECT 36.840 110.340 217.320 110.740 ;
    END
    PORT
      LAYER Metal3 ;
        RECT 36.840 137.300 217.320 137.700 ;
    END
    PORT
      LAYER Metal3 ;
        RECT 36.840 191.220 217.320 191.620 ;
    END
    PORT
      LAYER Metal3 ;
        RECT 36.840 245.140 217.320 245.540 ;
    END
    PORT
      LAYER Metal3 ;
        RECT 36.840 253.260 217.320 254.260 ;
    END
    PORT
      LAYER Metal3 ;
        RECT 36.840 246.750 217.510 247.030 ;
    END
    PORT
      LAYER Metal3 ;
        RECT 36.650 27.290 217.320 27.570 ;
    END
    PORT
      LAYER Metal3 ;
        RECT 36.840 83.380 217.320 83.780 ;
    END
  END vdd
  OBS
    LAYER Metal1 ;
      RECT 0.000 0.000 254.160 274.320 ;
    LAYER Metal2 ;
      RECT 0.000 0.000 254.160 274.320 ;
    LAYER Metal3 ;
      RECT 0.000 0.000 254.160 274.320 ;
  END
END DP8TRBlock_512x8
